##
## LEF for PtnCells ;
## created by Innovus v15.23-s045_1 on Fri Mar 20 02:54:40 2026
##

VERSION 5.8 ;

BUSBITCHARS "[]" ;
DIVIDERCHAR "/" ;

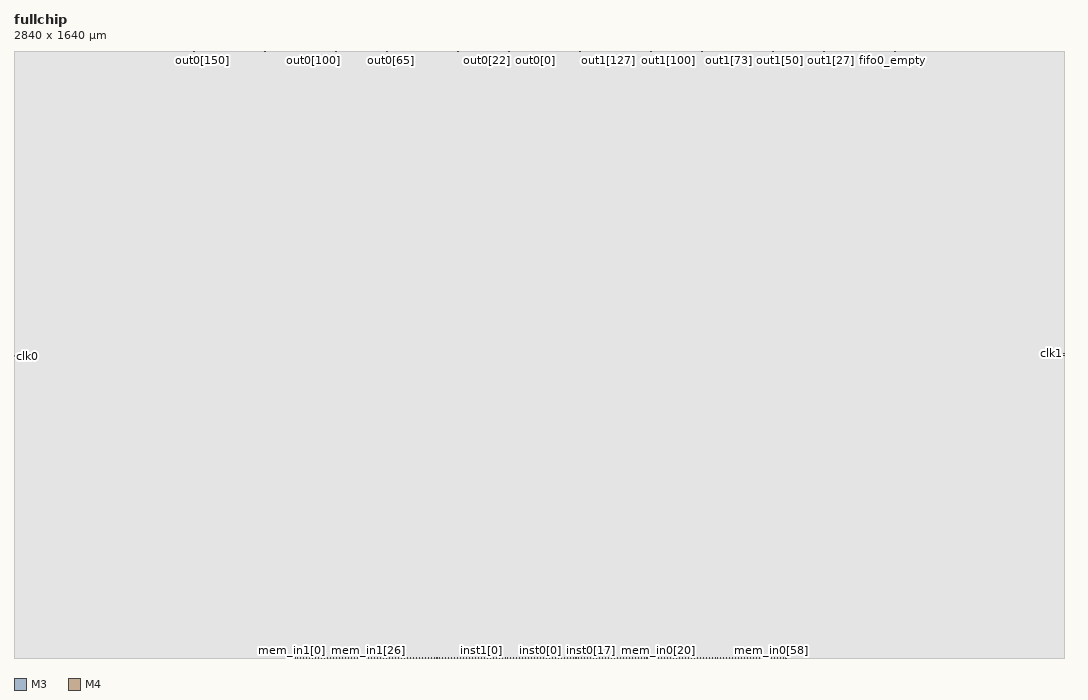
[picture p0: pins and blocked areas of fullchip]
MACRO fullchip
  CLASS BLOCK ;
  SIZE 2840.0000 BY 1640.0000 ;
  FOREIGN fullchip 0.0000 0.0000 ;
  ORIGIN 0 0 ;
  SYMMETRY X Y R90 ;
  PIN clk0
    DIRECTION INPUT ;
    USE SIGNAL ;
    PORT
      LAYER M3 ;
        RECT 0.0000 816.7500 0.5200 816.8500 ;
    END
  END clk0
  PIN clk1
    DIRECTION INPUT ;
    USE SIGNAL ;
    PORT
      LAYER M3 ;
        RECT 2839.4800 823.1500 2840.0000 823.2500 ;
    END
  END clk1
  PIN mem_in0[63]
    DIRECTION INPUT ;
    USE SIGNAL ;
    PORT
      LAYER M4 ;
        RECT 2088.0500 0.0000 2088.1500 0.5200 ;
    END
  END mem_in0[63]
  PIN mem_in0[62]
    DIRECTION INPUT ;
    USE SIGNAL ;
    PORT
      LAYER M4 ;
        RECT 2080.0500 0.0000 2080.1500 0.5200 ;
    END
  END mem_in0[62]
  PIN mem_in0[61]
    DIRECTION INPUT ;
    USE SIGNAL ;
    PORT
      LAYER M4 ;
        RECT 2072.0500 0.0000 2072.1500 0.5200 ;
    END
  END mem_in0[61]
  PIN mem_in0[60]
    DIRECTION INPUT ;
    USE SIGNAL ;
    PORT
      LAYER M4 ;
        RECT 2064.0500 0.0000 2064.1500 0.5200 ;
    END
  END mem_in0[60]
  PIN mem_in0[59]
    DIRECTION INPUT ;
    USE SIGNAL ;
    PORT
      LAYER M4 ;
        RECT 2056.0500 0.0000 2056.1500 0.5200 ;
    END
  END mem_in0[59]
  PIN mem_in0[58]
    DIRECTION INPUT ;
    USE SIGNAL ;
    PORT
      LAYER M4 ;
        RECT 2048.0500 0.0000 2048.1500 0.5200 ;
    END
  END mem_in0[58]
  PIN mem_in0[57]
    DIRECTION INPUT ;
    USE SIGNAL ;
    PORT
      LAYER M4 ;
        RECT 2040.0500 0.0000 2040.1500 0.5200 ;
    END
  END mem_in0[57]
  PIN mem_in0[56]
    DIRECTION INPUT ;
    USE SIGNAL ;
    PORT
      LAYER M4 ;
        RECT 2032.0500 0.0000 2032.1500 0.5200 ;
    END
  END mem_in0[56]
  PIN mem_in0[55]
    DIRECTION INPUT ;
    USE SIGNAL ;
    PORT
      LAYER M4 ;
        RECT 2024.0500 0.0000 2024.1500 0.5200 ;
    END
  END mem_in0[55]
  PIN mem_in0[54]
    DIRECTION INPUT ;
    USE SIGNAL ;
    PORT
      LAYER M4 ;
        RECT 2016.0500 0.0000 2016.1500 0.5200 ;
    END
  END mem_in0[54]
  PIN mem_in0[53]
    DIRECTION INPUT ;
    USE SIGNAL ;
    PORT
      LAYER M4 ;
        RECT 2008.0500 0.0000 2008.1500 0.5200 ;
    END
  END mem_in0[53]
  PIN mem_in0[52]
    DIRECTION INPUT ;
    USE SIGNAL ;
    PORT
      LAYER M4 ;
        RECT 2000.0500 0.0000 2000.1500 0.5200 ;
    END
  END mem_in0[52]
  PIN mem_in0[51]
    DIRECTION INPUT ;
    USE SIGNAL ;
    PORT
      LAYER M4 ;
        RECT 1992.0500 0.0000 1992.1500 0.5200 ;
    END
  END mem_in0[51]
  PIN mem_in0[50]
    DIRECTION INPUT ;
    USE SIGNAL ;
    PORT
      LAYER M4 ;
        RECT 1984.0500 0.0000 1984.1500 0.5200 ;
    END
  END mem_in0[50]
  PIN mem_in0[49]
    DIRECTION INPUT ;
    USE SIGNAL ;
    PORT
      LAYER M4 ;
        RECT 1976.0500 0.0000 1976.1500 0.5200 ;
    END
  END mem_in0[49]
  PIN mem_in0[48]
    DIRECTION INPUT ;
    USE SIGNAL ;
    PORT
      LAYER M4 ;
        RECT 1968.0500 0.0000 1968.1500 0.5200 ;
    END
  END mem_in0[48]
  PIN mem_in0[47]
    DIRECTION INPUT ;
    USE SIGNAL ;
    PORT
      LAYER M4 ;
        RECT 1960.0500 0.0000 1960.1500 0.5200 ;
    END
  END mem_in0[47]
  PIN mem_in0[46]
    DIRECTION INPUT ;
    USE SIGNAL ;
    PORT
      LAYER M4 ;
        RECT 1952.0500 0.0000 1952.1500 0.5200 ;
    END
  END mem_in0[46]
  PIN mem_in0[45]
    DIRECTION INPUT ;
    USE SIGNAL ;
    PORT
      LAYER M4 ;
        RECT 1944.0500 0.0000 1944.1500 0.5200 ;
    END
  END mem_in0[45]
  PIN mem_in0[44]
    DIRECTION INPUT ;
    USE SIGNAL ;
    PORT
      LAYER M4 ;
        RECT 1936.0500 0.0000 1936.1500 0.5200 ;
    END
  END mem_in0[44]
  PIN mem_in0[43]
    DIRECTION INPUT ;
    USE SIGNAL ;
    PORT
      LAYER M4 ;
        RECT 1928.0500 0.0000 1928.1500 0.5200 ;
    END
  END mem_in0[43]
  PIN mem_in0[42]
    DIRECTION INPUT ;
    USE SIGNAL ;
    PORT
      LAYER M4 ;
        RECT 1920.0500 0.0000 1920.1500 0.5200 ;
    END
  END mem_in0[42]
  PIN mem_in0[41]
    DIRECTION INPUT ;
    USE SIGNAL ;
    PORT
      LAYER M4 ;
        RECT 1912.0500 0.0000 1912.1500 0.5200 ;
    END
  END mem_in0[41]
  PIN mem_in0[40]
    DIRECTION INPUT ;
    USE SIGNAL ;
    PORT
      LAYER M4 ;
        RECT 1904.0500 0.0000 1904.1500 0.5200 ;
    END
  END mem_in0[40]
  PIN mem_in0[39]
    DIRECTION INPUT ;
    USE SIGNAL ;
    PORT
      LAYER M4 ;
        RECT 1896.0500 0.0000 1896.1500 0.5200 ;
    END
  END mem_in0[39]
  PIN mem_in0[38]
    DIRECTION INPUT ;
    USE SIGNAL ;
    PORT
      LAYER M4 ;
        RECT 1888.0500 0.0000 1888.1500 0.5200 ;
    END
  END mem_in0[38]
  PIN mem_in0[37]
    DIRECTION INPUT ;
    USE SIGNAL ;
    PORT
      LAYER M4 ;
        RECT 1880.0500 0.0000 1880.1500 0.5200 ;
    END
  END mem_in0[37]
  PIN mem_in0[36]
    DIRECTION INPUT ;
    USE SIGNAL ;
    PORT
      LAYER M4 ;
        RECT 1872.0500 0.0000 1872.1500 0.5200 ;
    END
  END mem_in0[36]
  PIN mem_in0[35]
    DIRECTION INPUT ;
    USE SIGNAL ;
    PORT
      LAYER M4 ;
        RECT 1864.0500 0.0000 1864.1500 0.5200 ;
    END
  END mem_in0[35]
  PIN mem_in0[34]
    DIRECTION INPUT ;
    USE SIGNAL ;
    PORT
      LAYER M4 ;
        RECT 1856.0500 0.0000 1856.1500 0.5200 ;
    END
  END mem_in0[34]
  PIN mem_in0[33]
    DIRECTION INPUT ;
    USE SIGNAL ;
    PORT
      LAYER M4 ;
        RECT 1848.0500 0.0000 1848.1500 0.5200 ;
    END
  END mem_in0[33]
  PIN mem_in0[32]
    DIRECTION INPUT ;
    USE SIGNAL ;
    PORT
      LAYER M4 ;
        RECT 1840.0500 0.0000 1840.1500 0.5200 ;
    END
  END mem_in0[32]
  PIN mem_in0[31]
    DIRECTION INPUT ;
    USE SIGNAL ;
    PORT
      LAYER M4 ;
        RECT 1832.0500 0.0000 1832.1500 0.5200 ;
    END
  END mem_in0[31]
  PIN mem_in0[30]
    DIRECTION INPUT ;
    USE SIGNAL ;
    PORT
      LAYER M4 ;
        RECT 1824.0500 0.0000 1824.1500 0.5200 ;
    END
  END mem_in0[30]
  PIN mem_in0[29]
    DIRECTION INPUT ;
    USE SIGNAL ;
    PORT
      LAYER M4 ;
        RECT 1816.0500 0.0000 1816.1500 0.5200 ;
    END
  END mem_in0[29]
  PIN mem_in0[28]
    DIRECTION INPUT ;
    USE SIGNAL ;
    PORT
      LAYER M4 ;
        RECT 1808.0500 0.0000 1808.1500 0.5200 ;
    END
  END mem_in0[28]
  PIN mem_in0[27]
    DIRECTION INPUT ;
    USE SIGNAL ;
    PORT
      LAYER M4 ;
        RECT 1800.0500 0.0000 1800.1500 0.5200 ;
    END
  END mem_in0[27]
  PIN mem_in0[26]
    DIRECTION INPUT ;
    USE SIGNAL ;
    PORT
      LAYER M4 ;
        RECT 1792.0500 0.0000 1792.1500 0.5200 ;
    END
  END mem_in0[26]
  PIN mem_in0[25]
    DIRECTION INPUT ;
    USE SIGNAL ;
    PORT
      LAYER M4 ;
        RECT 1784.0500 0.0000 1784.1500 0.5200 ;
    END
  END mem_in0[25]
  PIN mem_in0[24]
    DIRECTION INPUT ;
    USE SIGNAL ;
    PORT
      LAYER M4 ;
        RECT 1776.0500 0.0000 1776.1500 0.5200 ;
    END
  END mem_in0[24]
  PIN mem_in0[23]
    DIRECTION INPUT ;
    USE SIGNAL ;
    PORT
      LAYER M4 ;
        RECT 1768.0500 0.0000 1768.1500 0.5200 ;
    END
  END mem_in0[23]
  PIN mem_in0[22]
    DIRECTION INPUT ;
    USE SIGNAL ;
    PORT
      LAYER M4 ;
        RECT 1760.0500 0.0000 1760.1500 0.5200 ;
    END
  END mem_in0[22]
  PIN mem_in0[21]
    DIRECTION INPUT ;
    USE SIGNAL ;
    PORT
      LAYER M4 ;
        RECT 1752.0500 0.0000 1752.1500 0.5200 ;
    END
  END mem_in0[21]
  PIN mem_in0[20]
    DIRECTION INPUT ;
    USE SIGNAL ;
    PORT
      LAYER M4 ;
        RECT 1744.0500 0.0000 1744.1500 0.5200 ;
    END
  END mem_in0[20]
  PIN mem_in0[19]
    DIRECTION INPUT ;
    USE SIGNAL ;
    PORT
      LAYER M4 ;
        RECT 1736.0500 0.0000 1736.1500 0.5200 ;
    END
  END mem_in0[19]
  PIN mem_in0[18]
    DIRECTION INPUT ;
    USE SIGNAL ;
    PORT
      LAYER M4 ;
        RECT 1728.0500 0.0000 1728.1500 0.5200 ;
    END
  END mem_in0[18]
  PIN mem_in0[17]
    DIRECTION INPUT ;
    USE SIGNAL ;
    PORT
      LAYER M4 ;
        RECT 1720.0500 0.0000 1720.1500 0.5200 ;
    END
  END mem_in0[17]
  PIN mem_in0[16]
    DIRECTION INPUT ;
    USE SIGNAL ;
    PORT
      LAYER M4 ;
        RECT 1712.0500 0.0000 1712.1500 0.5200 ;
    END
  END mem_in0[16]
  PIN mem_in0[15]
    DIRECTION INPUT ;
    USE SIGNAL ;
    PORT
      LAYER M4 ;
        RECT 1704.0500 0.0000 1704.1500 0.5200 ;
    END
  END mem_in0[15]
  PIN mem_in0[14]
    DIRECTION INPUT ;
    USE SIGNAL ;
    PORT
      LAYER M4 ;
        RECT 1696.0500 0.0000 1696.1500 0.5200 ;
    END
  END mem_in0[14]
  PIN mem_in0[13]
    DIRECTION INPUT ;
    USE SIGNAL ;
    PORT
      LAYER M4 ;
        RECT 1688.0500 0.0000 1688.1500 0.5200 ;
    END
  END mem_in0[13]
  PIN mem_in0[12]
    DIRECTION INPUT ;
    USE SIGNAL ;
    PORT
      LAYER M4 ;
        RECT 1680.0500 0.0000 1680.1500 0.5200 ;
    END
  END mem_in0[12]
  PIN mem_in0[11]
    DIRECTION INPUT ;
    USE SIGNAL ;
    PORT
      LAYER M4 ;
        RECT 1672.0500 0.0000 1672.1500 0.5200 ;
    END
  END mem_in0[11]
  PIN mem_in0[10]
    DIRECTION INPUT ;
    USE SIGNAL ;
    PORT
      LAYER M4 ;
        RECT 1664.0500 0.0000 1664.1500 0.5200 ;
    END
  END mem_in0[10]
  PIN mem_in0[9]
    DIRECTION INPUT ;
    USE SIGNAL ;
    PORT
      LAYER M4 ;
        RECT 1656.0500 0.0000 1656.1500 0.5200 ;
    END
  END mem_in0[9]
  PIN mem_in0[8]
    DIRECTION INPUT ;
    USE SIGNAL ;
    PORT
      LAYER M4 ;
        RECT 1648.0500 0.0000 1648.1500 0.5200 ;
    END
  END mem_in0[8]
  PIN mem_in0[7]
    DIRECTION INPUT ;
    USE SIGNAL ;
    PORT
      LAYER M4 ;
        RECT 1640.0500 0.0000 1640.1500 0.5200 ;
    END
  END mem_in0[7]
  PIN mem_in0[6]
    DIRECTION INPUT ;
    USE SIGNAL ;
    PORT
      LAYER M4 ;
        RECT 1632.0500 0.0000 1632.1500 0.5200 ;
    END
  END mem_in0[6]
  PIN mem_in0[5]
    DIRECTION INPUT ;
    USE SIGNAL ;
    PORT
      LAYER M4 ;
        RECT 1624.0500 0.0000 1624.1500 0.5200 ;
    END
  END mem_in0[5]
  PIN mem_in0[4]
    DIRECTION INPUT ;
    USE SIGNAL ;
    PORT
      LAYER M4 ;
        RECT 1616.0500 0.0000 1616.1500 0.5200 ;
    END
  END mem_in0[4]
  PIN mem_in0[3]
    DIRECTION INPUT ;
    USE SIGNAL ;
    PORT
      LAYER M4 ;
        RECT 1608.0500 0.0000 1608.1500 0.5200 ;
    END
  END mem_in0[3]
  PIN mem_in0[2]
    DIRECTION INPUT ;
    USE SIGNAL ;
    PORT
      LAYER M4 ;
        RECT 1600.0500 0.0000 1600.1500 0.5200 ;
    END
  END mem_in0[2]
  PIN mem_in0[1]
    DIRECTION INPUT ;
    USE SIGNAL ;
    PORT
      LAYER M4 ;
        RECT 1592.0500 0.0000 1592.1500 0.5200 ;
    END
  END mem_in0[1]
  PIN mem_in0[0]
    DIRECTION INPUT ;
    USE SIGNAL ;
    PORT
      LAYER M4 ;
        RECT 1584.0500 0.0000 1584.1500 0.5200 ;
    END
  END mem_in0[0]
  PIN mem_in1[63]
    DIRECTION INPUT ;
    USE SIGNAL ;
    PORT
      LAYER M4 ;
        RECT 1256.0500 0.0000 1256.1500 0.5200 ;
    END
  END mem_in1[63]
  PIN mem_in1[62]
    DIRECTION INPUT ;
    USE SIGNAL ;
    PORT
      LAYER M4 ;
        RECT 1248.0500 0.0000 1248.1500 0.5200 ;
    END
  END mem_in1[62]
  PIN mem_in1[61]
    DIRECTION INPUT ;
    USE SIGNAL ;
    PORT
      LAYER M4 ;
        RECT 1240.0500 0.0000 1240.1500 0.5200 ;
    END
  END mem_in1[61]
  PIN mem_in1[60]
    DIRECTION INPUT ;
    USE SIGNAL ;
    PORT
      LAYER M4 ;
        RECT 1232.0500 0.0000 1232.1500 0.5200 ;
    END
  END mem_in1[60]
  PIN mem_in1[59]
    DIRECTION INPUT ;
    USE SIGNAL ;
    PORT
      LAYER M4 ;
        RECT 1224.0500 0.0000 1224.1500 0.5200 ;
    END
  END mem_in1[59]
  PIN mem_in1[58]
    DIRECTION INPUT ;
    USE SIGNAL ;
    PORT
      LAYER M4 ;
        RECT 1216.0500 0.0000 1216.1500 0.5200 ;
    END
  END mem_in1[58]
  PIN mem_in1[57]
    DIRECTION INPUT ;
    USE SIGNAL ;
    PORT
      LAYER M4 ;
        RECT 1208.0500 0.0000 1208.1500 0.5200 ;
    END
  END mem_in1[57]
  PIN mem_in1[56]
    DIRECTION INPUT ;
    USE SIGNAL ;
    PORT
      LAYER M4 ;
        RECT 1200.0500 0.0000 1200.1500 0.5200 ;
    END
  END mem_in1[56]
  PIN mem_in1[55]
    DIRECTION INPUT ;
    USE SIGNAL ;
    PORT
      LAYER M4 ;
        RECT 1192.0500 0.0000 1192.1500 0.5200 ;
    END
  END mem_in1[55]
  PIN mem_in1[54]
    DIRECTION INPUT ;
    USE SIGNAL ;
    PORT
      LAYER M4 ;
        RECT 1184.0500 0.0000 1184.1500 0.5200 ;
    END
  END mem_in1[54]
  PIN mem_in1[53]
    DIRECTION INPUT ;
    USE SIGNAL ;
    PORT
      LAYER M4 ;
        RECT 1176.0500 0.0000 1176.1500 0.5200 ;
    END
  END mem_in1[53]
  PIN mem_in1[52]
    DIRECTION INPUT ;
    USE SIGNAL ;
    PORT
      LAYER M4 ;
        RECT 1168.0500 0.0000 1168.1500 0.5200 ;
    END
  END mem_in1[52]
  PIN mem_in1[51]
    DIRECTION INPUT ;
    USE SIGNAL ;
    PORT
      LAYER M4 ;
        RECT 1160.0500 0.0000 1160.1500 0.5200 ;
    END
  END mem_in1[51]
  PIN mem_in1[50]
    DIRECTION INPUT ;
    USE SIGNAL ;
    PORT
      LAYER M4 ;
        RECT 1152.0500 0.0000 1152.1500 0.5200 ;
    END
  END mem_in1[50]
  PIN mem_in1[49]
    DIRECTION INPUT ;
    USE SIGNAL ;
    PORT
      LAYER M4 ;
        RECT 1144.0500 0.0000 1144.1500 0.5200 ;
    END
  END mem_in1[49]
  PIN mem_in1[48]
    DIRECTION INPUT ;
    USE SIGNAL ;
    PORT
      LAYER M4 ;
        RECT 1136.0500 0.0000 1136.1500 0.5200 ;
    END
  END mem_in1[48]
  PIN mem_in1[47]
    DIRECTION INPUT ;
    USE SIGNAL ;
    PORT
      LAYER M4 ;
        RECT 1128.0500 0.0000 1128.1500 0.5200 ;
    END
  END mem_in1[47]
  PIN mem_in1[46]
    DIRECTION INPUT ;
    USE SIGNAL ;
    PORT
      LAYER M4 ;
        RECT 1120.0500 0.0000 1120.1500 0.5200 ;
    END
  END mem_in1[46]
  PIN mem_in1[45]
    DIRECTION INPUT ;
    USE SIGNAL ;
    PORT
      LAYER M4 ;
        RECT 1112.0500 0.0000 1112.1500 0.5200 ;
    END
  END mem_in1[45]
  PIN mem_in1[44]
    DIRECTION INPUT ;
    USE SIGNAL ;
    PORT
      LAYER M4 ;
        RECT 1104.0500 0.0000 1104.1500 0.5200 ;
    END
  END mem_in1[44]
  PIN mem_in1[43]
    DIRECTION INPUT ;
    USE SIGNAL ;
    PORT
      LAYER M4 ;
        RECT 1096.0500 0.0000 1096.1500 0.5200 ;
    END
  END mem_in1[43]
  PIN mem_in1[42]
    DIRECTION INPUT ;
    USE SIGNAL ;
    PORT
      LAYER M4 ;
        RECT 1088.0500 0.0000 1088.1500 0.5200 ;
    END
  END mem_in1[42]
  PIN mem_in1[41]
    DIRECTION INPUT ;
    USE SIGNAL ;
    PORT
      LAYER M4 ;
        RECT 1080.0500 0.0000 1080.1500 0.5200 ;
    END
  END mem_in1[41]
  PIN mem_in1[40]
    DIRECTION INPUT ;
    USE SIGNAL ;
    PORT
      LAYER M4 ;
        RECT 1072.0500 0.0000 1072.1500 0.5200 ;
    END
  END mem_in1[40]
  PIN mem_in1[39]
    DIRECTION INPUT ;
    USE SIGNAL ;
    PORT
      LAYER M4 ;
        RECT 1064.0500 0.0000 1064.1500 0.5200 ;
    END
  END mem_in1[39]
  PIN mem_in1[38]
    DIRECTION INPUT ;
    USE SIGNAL ;
    PORT
      LAYER M4 ;
        RECT 1056.0500 0.0000 1056.1500 0.5200 ;
    END
  END mem_in1[38]
  PIN mem_in1[37]
    DIRECTION INPUT ;
    USE SIGNAL ;
    PORT
      LAYER M4 ;
        RECT 1048.0500 0.0000 1048.1500 0.5200 ;
    END
  END mem_in1[37]
  PIN mem_in1[36]
    DIRECTION INPUT ;
    USE SIGNAL ;
    PORT
      LAYER M4 ;
        RECT 1040.0500 0.0000 1040.1500 0.5200 ;
    END
  END mem_in1[36]
  PIN mem_in1[35]
    DIRECTION INPUT ;
    USE SIGNAL ;
    PORT
      LAYER M4 ;
        RECT 1032.0500 0.0000 1032.1500 0.5200 ;
    END
  END mem_in1[35]
  PIN mem_in1[34]
    DIRECTION INPUT ;
    USE SIGNAL ;
    PORT
      LAYER M4 ;
        RECT 1024.0500 0.0000 1024.1500 0.5200 ;
    END
  END mem_in1[34]
  PIN mem_in1[33]
    DIRECTION INPUT ;
    USE SIGNAL ;
    PORT
      LAYER M4 ;
        RECT 1016.0500 0.0000 1016.1500 0.5200 ;
    END
  END mem_in1[33]
  PIN mem_in1[32]
    DIRECTION INPUT ;
    USE SIGNAL ;
    PORT
      LAYER M4 ;
        RECT 1008.0500 0.0000 1008.1500 0.5200 ;
    END
  END mem_in1[32]
  PIN mem_in1[31]
    DIRECTION INPUT ;
    USE SIGNAL ;
    PORT
      LAYER M4 ;
        RECT 1000.0500 0.0000 1000.1500 0.5200 ;
    END
  END mem_in1[31]
  PIN mem_in1[30]
    DIRECTION INPUT ;
    USE SIGNAL ;
    PORT
      LAYER M4 ;
        RECT 992.0500 0.0000 992.1500 0.5200 ;
    END
  END mem_in1[30]
  PIN mem_in1[29]
    DIRECTION INPUT ;
    USE SIGNAL ;
    PORT
      LAYER M4 ;
        RECT 984.0500 0.0000 984.1500 0.5200 ;
    END
  END mem_in1[29]
  PIN mem_in1[28]
    DIRECTION INPUT ;
    USE SIGNAL ;
    PORT
      LAYER M4 ;
        RECT 976.0500 0.0000 976.1500 0.5200 ;
    END
  END mem_in1[28]
  PIN mem_in1[27]
    DIRECTION INPUT ;
    USE SIGNAL ;
    PORT
      LAYER M4 ;
        RECT 968.0500 0.0000 968.1500 0.5200 ;
    END
  END mem_in1[27]
  PIN mem_in1[26]
    DIRECTION INPUT ;
    USE SIGNAL ;
    PORT
      LAYER M4 ;
        RECT 960.0500 0.0000 960.1500 0.5200 ;
    END
  END mem_in1[26]
  PIN mem_in1[25]
    DIRECTION INPUT ;
    USE SIGNAL ;
    PORT
      LAYER M4 ;
        RECT 952.0500 0.0000 952.1500 0.5200 ;
    END
  END mem_in1[25]
  PIN mem_in1[24]
    DIRECTION INPUT ;
    USE SIGNAL ;
    PORT
      LAYER M4 ;
        RECT 944.0500 0.0000 944.1500 0.5200 ;
    END
  END mem_in1[24]
  PIN mem_in1[23]
    DIRECTION INPUT ;
    USE SIGNAL ;
    PORT
      LAYER M4 ;
        RECT 936.0500 0.0000 936.1500 0.5200 ;
    END
  END mem_in1[23]
  PIN mem_in1[22]
    DIRECTION INPUT ;
    USE SIGNAL ;
    PORT
      LAYER M4 ;
        RECT 928.0500 0.0000 928.1500 0.5200 ;
    END
  END mem_in1[22]
  PIN mem_in1[21]
    DIRECTION INPUT ;
    USE SIGNAL ;
    PORT
      LAYER M4 ;
        RECT 920.0500 0.0000 920.1500 0.5200 ;
    END
  END mem_in1[21]
  PIN mem_in1[20]
    DIRECTION INPUT ;
    USE SIGNAL ;
    PORT
      LAYER M4 ;
        RECT 912.0500 0.0000 912.1500 0.5200 ;
    END
  END mem_in1[20]
  PIN mem_in1[19]
    DIRECTION INPUT ;
    USE SIGNAL ;
    PORT
      LAYER M4 ;
        RECT 904.0500 0.0000 904.1500 0.5200 ;
    END
  END mem_in1[19]
  PIN mem_in1[18]
    DIRECTION INPUT ;
    USE SIGNAL ;
    PORT
      LAYER M4 ;
        RECT 896.0500 0.0000 896.1500 0.5200 ;
    END
  END mem_in1[18]
  PIN mem_in1[17]
    DIRECTION INPUT ;
    USE SIGNAL ;
    PORT
      LAYER M4 ;
        RECT 888.0500 0.0000 888.1500 0.5200 ;
    END
  END mem_in1[17]
  PIN mem_in1[16]
    DIRECTION INPUT ;
    USE SIGNAL ;
    PORT
      LAYER M4 ;
        RECT 880.0500 0.0000 880.1500 0.5200 ;
    END
  END mem_in1[16]
  PIN mem_in1[15]
    DIRECTION INPUT ;
    USE SIGNAL ;
    PORT
      LAYER M4 ;
        RECT 872.0500 0.0000 872.1500 0.5200 ;
    END
  END mem_in1[15]
  PIN mem_in1[14]
    DIRECTION INPUT ;
    USE SIGNAL ;
    PORT
      LAYER M4 ;
        RECT 864.0500 0.0000 864.1500 0.5200 ;
    END
  END mem_in1[14]
  PIN mem_in1[13]
    DIRECTION INPUT ;
    USE SIGNAL ;
    PORT
      LAYER M4 ;
        RECT 856.0500 0.0000 856.1500 0.5200 ;
    END
  END mem_in1[13]
  PIN mem_in1[12]
    DIRECTION INPUT ;
    USE SIGNAL ;
    PORT
      LAYER M4 ;
        RECT 848.0500 0.0000 848.1500 0.5200 ;
    END
  END mem_in1[12]
  PIN mem_in1[11]
    DIRECTION INPUT ;
    USE SIGNAL ;
    PORT
      LAYER M4 ;
        RECT 840.0500 0.0000 840.1500 0.5200 ;
    END
  END mem_in1[11]
  PIN mem_in1[10]
    DIRECTION INPUT ;
    USE SIGNAL ;
    PORT
      LAYER M4 ;
        RECT 832.0500 0.0000 832.1500 0.5200 ;
    END
  END mem_in1[10]
  PIN mem_in1[9]
    DIRECTION INPUT ;
    USE SIGNAL ;
    PORT
      LAYER M4 ;
        RECT 824.0500 0.0000 824.1500 0.5200 ;
    END
  END mem_in1[9]
  PIN mem_in1[8]
    DIRECTION INPUT ;
    USE SIGNAL ;
    PORT
      LAYER M4 ;
        RECT 816.0500 0.0000 816.1500 0.5200 ;
    END
  END mem_in1[8]
  PIN mem_in1[7]
    DIRECTION INPUT ;
    USE SIGNAL ;
    PORT
      LAYER M4 ;
        RECT 808.0500 0.0000 808.1500 0.5200 ;
    END
  END mem_in1[7]
  PIN mem_in1[6]
    DIRECTION INPUT ;
    USE SIGNAL ;
    PORT
      LAYER M4 ;
        RECT 800.0500 0.0000 800.1500 0.5200 ;
    END
  END mem_in1[6]
  PIN mem_in1[5]
    DIRECTION INPUT ;
    USE SIGNAL ;
    PORT
      LAYER M4 ;
        RECT 792.0500 0.0000 792.1500 0.5200 ;
    END
  END mem_in1[5]
  PIN mem_in1[4]
    DIRECTION INPUT ;
    USE SIGNAL ;
    PORT
      LAYER M4 ;
        RECT 784.0500 0.0000 784.1500 0.5200 ;
    END
  END mem_in1[4]
  PIN mem_in1[3]
    DIRECTION INPUT ;
    USE SIGNAL ;
    PORT
      LAYER M4 ;
        RECT 776.0500 0.0000 776.1500 0.5200 ;
    END
  END mem_in1[3]
  PIN mem_in1[2]
    DIRECTION INPUT ;
    USE SIGNAL ;
    PORT
      LAYER M4 ;
        RECT 768.0500 0.0000 768.1500 0.5200 ;
    END
  END mem_in1[2]
  PIN mem_in1[1]
    DIRECTION INPUT ;
    USE SIGNAL ;
    PORT
      LAYER M4 ;
        RECT 760.0500 0.0000 760.1500 0.5200 ;
    END
  END mem_in1[1]
  PIN mem_in1[0]
    DIRECTION INPUT ;
    USE SIGNAL ;
    PORT
      LAYER M4 ;
        RECT 752.0500 0.0000 752.1500 0.5200 ;
    END
  END mem_in1[0]
  PIN inst0[19]
    DIRECTION INPUT ;
    USE SIGNAL ;
    PORT
      LAYER M4 ;
        RECT 1576.0500 0.0000 1576.1500 0.5200 ;
    END
  END inst0[19]
  PIN inst0[18]
    DIRECTION INPUT ;
    USE SIGNAL ;
    PORT
      LAYER M4 ;
        RECT 1568.0500 0.0000 1568.1500 0.5200 ;
    END
  END inst0[18]
  PIN inst0[17]
    DIRECTION INPUT ;
    USE SIGNAL ;
    PORT
      LAYER M4 ;
        RECT 1560.0500 0.0000 1560.1500 0.5200 ;
    END
  END inst0[17]
  PIN inst0[16]
    DIRECTION INPUT ;
    USE SIGNAL ;
    PORT
      LAYER M4 ;
        RECT 1552.0500 0.0000 1552.1500 0.5200 ;
    END
  END inst0[16]
  PIN inst0[15]
    DIRECTION INPUT ;
    USE SIGNAL ;
    PORT
      LAYER M4 ;
        RECT 1544.0500 0.0000 1544.1500 0.5200 ;
    END
  END inst0[15]
  PIN inst0[14]
    DIRECTION INPUT ;
    USE SIGNAL ;
    PORT
      LAYER M4 ;
        RECT 1536.0500 0.0000 1536.1500 0.5200 ;
    END
  END inst0[14]
  PIN inst0[13]
    DIRECTION INPUT ;
    USE SIGNAL ;
    PORT
      LAYER M4 ;
        RECT 1528.0500 0.0000 1528.1500 0.5200 ;
    END
  END inst0[13]
  PIN inst0[12]
    DIRECTION INPUT ;
    USE SIGNAL ;
    PORT
      LAYER M4 ;
        RECT 1520.0500 0.0000 1520.1500 0.5200 ;
    END
  END inst0[12]
  PIN inst0[11]
    DIRECTION INPUT ;
    USE SIGNAL ;
    PORT
      LAYER M4 ;
        RECT 1512.0500 0.0000 1512.1500 0.5200 ;
    END
  END inst0[11]
  PIN inst0[10]
    DIRECTION INPUT ;
    USE SIGNAL ;
    PORT
      LAYER M4 ;
        RECT 1504.0500 0.0000 1504.1500 0.5200 ;
    END
  END inst0[10]
  PIN inst0[9]
    DIRECTION INPUT ;
    USE SIGNAL ;
    PORT
      LAYER M4 ;
        RECT 1496.0500 0.0000 1496.1500 0.5200 ;
    END
  END inst0[9]
  PIN inst0[8]
    DIRECTION INPUT ;
    USE SIGNAL ;
    PORT
      LAYER M4 ;
        RECT 1488.0500 0.0000 1488.1500 0.5200 ;
    END
  END inst0[8]
  PIN inst0[7]
    DIRECTION INPUT ;
    USE SIGNAL ;
    PORT
      LAYER M4 ;
        RECT 1480.0500 0.0000 1480.1500 0.5200 ;
    END
  END inst0[7]
  PIN inst0[6]
    DIRECTION INPUT ;
    USE SIGNAL ;
    PORT
      LAYER M4 ;
        RECT 1472.0500 0.0000 1472.1500 0.5200 ;
    END
  END inst0[6]
  PIN inst0[5]
    DIRECTION INPUT ;
    USE SIGNAL ;
    PORT
      LAYER M4 ;
        RECT 1464.0500 0.0000 1464.1500 0.5200 ;
    END
  END inst0[5]
  PIN inst0[4]
    DIRECTION INPUT ;
    USE SIGNAL ;
    PORT
      LAYER M4 ;
        RECT 1456.0500 0.0000 1456.1500 0.5200 ;
    END
  END inst0[4]
  PIN inst0[3]
    DIRECTION INPUT ;
    USE SIGNAL ;
    PORT
      LAYER M4 ;
        RECT 1448.0500 0.0000 1448.1500 0.5200 ;
    END
  END inst0[3]
  PIN inst0[2]
    DIRECTION INPUT ;
    USE SIGNAL ;
    PORT
      LAYER M4 ;
        RECT 1440.0500 0.0000 1440.1500 0.5200 ;
    END
  END inst0[2]
  PIN inst0[1]
    DIRECTION INPUT ;
    USE SIGNAL ;
    PORT
      LAYER M4 ;
        RECT 1432.0500 0.0000 1432.1500 0.5200 ;
    END
  END inst0[1]
  PIN inst0[0]
    DIRECTION INPUT ;
    USE SIGNAL ;
    PORT
      LAYER M4 ;
        RECT 1424.0500 0.0000 1424.1500 0.5200 ;
    END
  END inst0[0]
  PIN inst1[19]
    DIRECTION INPUT ;
    USE SIGNAL ;
    PORT
      LAYER M4 ;
        RECT 1416.0500 0.0000 1416.1500 0.5200 ;
    END
  END inst1[19]
  PIN inst1[18]
    DIRECTION INPUT ;
    USE SIGNAL ;
    PORT
      LAYER M4 ;
        RECT 1408.0500 0.0000 1408.1500 0.5200 ;
    END
  END inst1[18]
  PIN inst1[17]
    DIRECTION INPUT ;
    USE SIGNAL ;
    PORT
      LAYER M4 ;
        RECT 1400.0500 0.0000 1400.1500 0.5200 ;
    END
  END inst1[17]
  PIN inst1[16]
    DIRECTION INPUT ;
    USE SIGNAL ;
    PORT
      LAYER M4 ;
        RECT 1392.0500 0.0000 1392.1500 0.5200 ;
    END
  END inst1[16]
  PIN inst1[15]
    DIRECTION INPUT ;
    USE SIGNAL ;
    PORT
      LAYER M4 ;
        RECT 1384.0500 0.0000 1384.1500 0.5200 ;
    END
  END inst1[15]
  PIN inst1[14]
    DIRECTION INPUT ;
    USE SIGNAL ;
    PORT
      LAYER M4 ;
        RECT 1376.0500 0.0000 1376.1500 0.5200 ;
    END
  END inst1[14]
  PIN inst1[13]
    DIRECTION INPUT ;
    USE SIGNAL ;
    PORT
      LAYER M4 ;
        RECT 1368.0500 0.0000 1368.1500 0.5200 ;
    END
  END inst1[13]
  PIN inst1[12]
    DIRECTION INPUT ;
    USE SIGNAL ;
    PORT
      LAYER M4 ;
        RECT 1360.0500 0.0000 1360.1500 0.5200 ;
    END
  END inst1[12]
  PIN inst1[11]
    DIRECTION INPUT ;
    USE SIGNAL ;
    PORT
      LAYER M4 ;
        RECT 1352.0500 0.0000 1352.1500 0.5200 ;
    END
  END inst1[11]
  PIN inst1[10]
    DIRECTION INPUT ;
    USE SIGNAL ;
    PORT
      LAYER M4 ;
        RECT 1344.0500 0.0000 1344.1500 0.5200 ;
    END
  END inst1[10]
  PIN inst1[9]
    DIRECTION INPUT ;
    USE SIGNAL ;
    PORT
      LAYER M4 ;
        RECT 1336.0500 0.0000 1336.1500 0.5200 ;
    END
  END inst1[9]
  PIN inst1[8]
    DIRECTION INPUT ;
    USE SIGNAL ;
    PORT
      LAYER M4 ;
        RECT 1328.0500 0.0000 1328.1500 0.5200 ;
    END
  END inst1[8]
  PIN inst1[7]
    DIRECTION INPUT ;
    USE SIGNAL ;
    PORT
      LAYER M4 ;
        RECT 1320.0500 0.0000 1320.1500 0.5200 ;
    END
  END inst1[7]
  PIN inst1[6]
    DIRECTION INPUT ;
    USE SIGNAL ;
    PORT
      LAYER M4 ;
        RECT 1312.0500 0.0000 1312.1500 0.5200 ;
    END
  END inst1[6]
  PIN inst1[5]
    DIRECTION INPUT ;
    USE SIGNAL ;
    PORT
      LAYER M4 ;
        RECT 1304.0500 0.0000 1304.1500 0.5200 ;
    END
  END inst1[5]
  PIN inst1[4]
    DIRECTION INPUT ;
    USE SIGNAL ;
    PORT
      LAYER M4 ;
        RECT 1296.0500 0.0000 1296.1500 0.5200 ;
    END
  END inst1[4]
  PIN inst1[3]
    DIRECTION INPUT ;
    USE SIGNAL ;
    PORT
      LAYER M4 ;
        RECT 1288.0500 0.0000 1288.1500 0.5200 ;
    END
  END inst1[3]
  PIN inst1[2]
    DIRECTION INPUT ;
    USE SIGNAL ;
    PORT
      LAYER M4 ;
        RECT 1280.0500 0.0000 1280.1500 0.5200 ;
    END
  END inst1[2]
  PIN inst1[1]
    DIRECTION INPUT ;
    USE SIGNAL ;
    PORT
      LAYER M4 ;
        RECT 1272.0500 0.0000 1272.1500 0.5200 ;
    END
  END inst1[1]
  PIN inst1[0]
    DIRECTION INPUT ;
    USE SIGNAL ;
    PORT
      LAYER M4 ;
        RECT 1264.0500 0.0000 1264.1500 0.5200 ;
    END
  END inst1[0]
  PIN reset0
    DIRECTION INPUT ;
    USE SIGNAL ;
    PORT
      LAYER M3 ;
        RECT 0.0000 822.7500 0.5200 822.8500 ;
    END
  END reset0
  PIN reset1
    DIRECTION INPUT ;
    USE SIGNAL ;
    PORT
      LAYER M3 ;
        RECT 2839.4800 817.1500 2840.0000 817.2500 ;
    END
  END reset1
  PIN out0[159]
    DIRECTION OUTPUT ;
    USE SIGNAL ;
    PORT
      LAYER M4 ;
        RECT 456.8500 1639.4800 456.9500 1640.0000 ;
    END
  END out0[159]
  PIN out0[158]
    DIRECTION OUTPUT ;
    USE SIGNAL ;
    PORT
      LAYER M4 ;
        RECT 462.8500 1639.4800 462.9500 1640.0000 ;
    END
  END out0[158]
  PIN out0[157]
    DIRECTION OUTPUT ;
    USE SIGNAL ;
    PORT
      LAYER M4 ;
        RECT 468.8500 1639.4800 468.9500 1640.0000 ;
    END
  END out0[157]
  PIN out0[156]
    DIRECTION OUTPUT ;
    USE SIGNAL ;
    PORT
      LAYER M4 ;
        RECT 474.8500 1639.4800 474.9500 1640.0000 ;
    END
  END out0[156]
  PIN out0[155]
    DIRECTION OUTPUT ;
    USE SIGNAL ;
    PORT
      LAYER M4 ;
        RECT 480.8500 1639.4800 480.9500 1640.0000 ;
    END
  END out0[155]
  PIN out0[154]
    DIRECTION OUTPUT ;
    USE SIGNAL ;
    PORT
      LAYER M4 ;
        RECT 486.8500 1639.4800 486.9500 1640.0000 ;
    END
  END out0[154]
  PIN out0[153]
    DIRECTION OUTPUT ;
    USE SIGNAL ;
    PORT
      LAYER M4 ;
        RECT 492.8500 1639.4800 492.9500 1640.0000 ;
    END
  END out0[153]
  PIN out0[152]
    DIRECTION OUTPUT ;
    USE SIGNAL ;
    PORT
      LAYER M4 ;
        RECT 498.8500 1639.4800 498.9500 1640.0000 ;
    END
  END out0[152]
  PIN out0[151]
    DIRECTION OUTPUT ;
    USE SIGNAL ;
    PORT
      LAYER M4 ;
        RECT 504.8500 1639.4800 504.9500 1640.0000 ;
    END
  END out0[151]
  PIN out0[150]
    DIRECTION OUTPUT ;
    USE SIGNAL ;
    PORT
      LAYER M4 ;
        RECT 510.8500 1639.4800 510.9500 1640.0000 ;
    END
  END out0[150]
  PIN out0[149]
    DIRECTION OUTPUT ;
    USE SIGNAL ;
    PORT
      LAYER M4 ;
        RECT 516.8500 1639.4800 516.9500 1640.0000 ;
    END
  END out0[149]
  PIN out0[148]
    DIRECTION OUTPUT ;
    USE SIGNAL ;
    PORT
      LAYER M4 ;
        RECT 522.8500 1639.4800 522.9500 1640.0000 ;
    END
  END out0[148]
  PIN out0[147]
    DIRECTION OUTPUT ;
    USE SIGNAL ;
    PORT
      LAYER M4 ;
        RECT 528.8500 1639.4800 528.9500 1640.0000 ;
    END
  END out0[147]
  PIN out0[146]
    DIRECTION OUTPUT ;
    USE SIGNAL ;
    PORT
      LAYER M4 ;
        RECT 534.8500 1639.4800 534.9500 1640.0000 ;
    END
  END out0[146]
  PIN out0[145]
    DIRECTION OUTPUT ;
    USE SIGNAL ;
    PORT
      LAYER M4 ;
        RECT 540.8500 1639.4800 540.9500 1640.0000 ;
    END
  END out0[145]
  PIN out0[144]
    DIRECTION OUTPUT ;
    USE SIGNAL ;
    PORT
      LAYER M4 ;
        RECT 546.8500 1639.4800 546.9500 1640.0000 ;
    END
  END out0[144]
  PIN out0[143]
    DIRECTION OUTPUT ;
    USE SIGNAL ;
    PORT
      LAYER M4 ;
        RECT 552.8500 1639.4800 552.9500 1640.0000 ;
    END
  END out0[143]
  PIN out0[142]
    DIRECTION OUTPUT ;
    USE SIGNAL ;
    PORT
      LAYER M4 ;
        RECT 558.8500 1639.4800 558.9500 1640.0000 ;
    END
  END out0[142]
  PIN out0[141]
    DIRECTION OUTPUT ;
    USE SIGNAL ;
    PORT
      LAYER M4 ;
        RECT 564.8500 1639.4800 564.9500 1640.0000 ;
    END
  END out0[141]
  PIN out0[140]
    DIRECTION OUTPUT ;
    USE SIGNAL ;
    PORT
      LAYER M4 ;
        RECT 570.8500 1639.4800 570.9500 1640.0000 ;
    END
  END out0[140]
  PIN out0[139]
    DIRECTION OUTPUT ;
    USE SIGNAL ;
    PORT
      LAYER M4 ;
        RECT 576.8500 1639.4800 576.9500 1640.0000 ;
    END
  END out0[139]
  PIN out0[138]
    DIRECTION OUTPUT ;
    USE SIGNAL ;
    PORT
      LAYER M4 ;
        RECT 582.8500 1639.4800 582.9500 1640.0000 ;
    END
  END out0[138]
  PIN out0[137]
    DIRECTION OUTPUT ;
    USE SIGNAL ;
    PORT
      LAYER M4 ;
        RECT 588.8500 1639.4800 588.9500 1640.0000 ;
    END
  END out0[137]
  PIN out0[136]
    DIRECTION OUTPUT ;
    USE SIGNAL ;
    PORT
      LAYER M4 ;
        RECT 594.8500 1639.4800 594.9500 1640.0000 ;
    END
  END out0[136]
  PIN out0[135]
    DIRECTION OUTPUT ;
    USE SIGNAL ;
    PORT
      LAYER M4 ;
        RECT 600.8500 1639.4800 600.9500 1640.0000 ;
    END
  END out0[135]
  PIN out0[134]
    DIRECTION OUTPUT ;
    USE SIGNAL ;
    PORT
      LAYER M4 ;
        RECT 606.8500 1639.4800 606.9500 1640.0000 ;
    END
  END out0[134]
  PIN out0[133]
    DIRECTION OUTPUT ;
    USE SIGNAL ;
    PORT
      LAYER M4 ;
        RECT 612.8500 1639.4800 612.9500 1640.0000 ;
    END
  END out0[133]
  PIN out0[132]
    DIRECTION OUTPUT ;
    USE SIGNAL ;
    PORT
      LAYER M4 ;
        RECT 618.8500 1639.4800 618.9500 1640.0000 ;
    END
  END out0[132]
  PIN out0[131]
    DIRECTION OUTPUT ;
    USE SIGNAL ;
    PORT
      LAYER M4 ;
        RECT 624.8500 1639.4800 624.9500 1640.0000 ;
    END
  END out0[131]
  PIN out0[130]
    DIRECTION OUTPUT ;
    USE SIGNAL ;
    PORT
      LAYER M4 ;
        RECT 630.8500 1639.4800 630.9500 1640.0000 ;
    END
  END out0[130]
  PIN out0[129]
    DIRECTION OUTPUT ;
    USE SIGNAL ;
    PORT
      LAYER M4 ;
        RECT 636.8500 1639.4800 636.9500 1640.0000 ;
    END
  END out0[129]
  PIN out0[128]
    DIRECTION OUTPUT ;
    USE SIGNAL ;
    PORT
      LAYER M4 ;
        RECT 642.8500 1639.4800 642.9500 1640.0000 ;
    END
  END out0[128]
  PIN out0[127]
    DIRECTION OUTPUT ;
    USE SIGNAL ;
    PORT
      LAYER M4 ;
        RECT 648.8500 1639.4800 648.9500 1640.0000 ;
    END
  END out0[127]
  PIN out0[126]
    DIRECTION OUTPUT ;
    USE SIGNAL ;
    PORT
      LAYER M4 ;
        RECT 654.8500 1639.4800 654.9500 1640.0000 ;
    END
  END out0[126]
  PIN out0[125]
    DIRECTION OUTPUT ;
    USE SIGNAL ;
    PORT
      LAYER M4 ;
        RECT 660.8500 1639.4800 660.9500 1640.0000 ;
    END
  END out0[125]
  PIN out0[124]
    DIRECTION OUTPUT ;
    USE SIGNAL ;
    PORT
      LAYER M4 ;
        RECT 666.8500 1639.4800 666.9500 1640.0000 ;
    END
  END out0[124]
  PIN out0[123]
    DIRECTION OUTPUT ;
    USE SIGNAL ;
    PORT
      LAYER M4 ;
        RECT 672.8500 1639.4800 672.9500 1640.0000 ;
    END
  END out0[123]
  PIN out0[122]
    DIRECTION OUTPUT ;
    USE SIGNAL ;
    PORT
      LAYER M4 ;
        RECT 678.8500 1639.4800 678.9500 1640.0000 ;
    END
  END out0[122]
  PIN out0[121]
    DIRECTION OUTPUT ;
    USE SIGNAL ;
    PORT
      LAYER M4 ;
        RECT 684.8500 1639.4800 684.9500 1640.0000 ;
    END
  END out0[121]
  PIN out0[120]
    DIRECTION OUTPUT ;
    USE SIGNAL ;
    PORT
      LAYER M4 ;
        RECT 690.8500 1639.4800 690.9500 1640.0000 ;
    END
  END out0[120]
  PIN out0[119]
    DIRECTION OUTPUT ;
    USE SIGNAL ;
    PORT
      LAYER M4 ;
        RECT 696.8500 1639.4800 696.9500 1640.0000 ;
    END
  END out0[119]
  PIN out0[118]
    DIRECTION OUTPUT ;
    USE SIGNAL ;
    PORT
      LAYER M4 ;
        RECT 702.8500 1639.4800 702.9500 1640.0000 ;
    END
  END out0[118]
  PIN out0[117]
    DIRECTION OUTPUT ;
    USE SIGNAL ;
    PORT
      LAYER M4 ;
        RECT 708.8500 1639.4800 708.9500 1640.0000 ;
    END
  END out0[117]
  PIN out0[116]
    DIRECTION OUTPUT ;
    USE SIGNAL ;
    PORT
      LAYER M4 ;
        RECT 714.8500 1639.4800 714.9500 1640.0000 ;
    END
  END out0[116]
  PIN out0[115]
    DIRECTION OUTPUT ;
    USE SIGNAL ;
    PORT
      LAYER M4 ;
        RECT 720.8500 1639.4800 720.9500 1640.0000 ;
    END
  END out0[115]
  PIN out0[114]
    DIRECTION OUTPUT ;
    USE SIGNAL ;
    PORT
      LAYER M4 ;
        RECT 726.8500 1639.4800 726.9500 1640.0000 ;
    END
  END out0[114]
  PIN out0[113]
    DIRECTION OUTPUT ;
    USE SIGNAL ;
    PORT
      LAYER M4 ;
        RECT 732.8500 1639.4800 732.9500 1640.0000 ;
    END
  END out0[113]
  PIN out0[112]
    DIRECTION OUTPUT ;
    USE SIGNAL ;
    PORT
      LAYER M4 ;
        RECT 738.8500 1639.4800 738.9500 1640.0000 ;
    END
  END out0[112]
  PIN out0[111]
    DIRECTION OUTPUT ;
    USE SIGNAL ;
    PORT
      LAYER M4 ;
        RECT 744.8500 1639.4800 744.9500 1640.0000 ;
    END
  END out0[111]
  PIN out0[110]
    DIRECTION OUTPUT ;
    USE SIGNAL ;
    PORT
      LAYER M4 ;
        RECT 750.8500 1639.4800 750.9500 1640.0000 ;
    END
  END out0[110]
  PIN out0[109]
    DIRECTION OUTPUT ;
    USE SIGNAL ;
    PORT
      LAYER M4 ;
        RECT 756.8500 1639.4800 756.9500 1640.0000 ;
    END
  END out0[109]
  PIN out0[108]
    DIRECTION OUTPUT ;
    USE SIGNAL ;
    PORT
      LAYER M4 ;
        RECT 762.8500 1639.4800 762.9500 1640.0000 ;
    END
  END out0[108]
  PIN out0[107]
    DIRECTION OUTPUT ;
    USE SIGNAL ;
    PORT
      LAYER M4 ;
        RECT 768.8500 1639.4800 768.9500 1640.0000 ;
    END
  END out0[107]
  PIN out0[106]
    DIRECTION OUTPUT ;
    USE SIGNAL ;
    PORT
      LAYER M4 ;
        RECT 774.8500 1639.4800 774.9500 1640.0000 ;
    END
  END out0[106]
  PIN out0[105]
    DIRECTION OUTPUT ;
    USE SIGNAL ;
    PORT
      LAYER M4 ;
        RECT 780.8500 1639.4800 780.9500 1640.0000 ;
    END
  END out0[105]
  PIN out0[104]
    DIRECTION OUTPUT ;
    USE SIGNAL ;
    PORT
      LAYER M4 ;
        RECT 786.8500 1639.4800 786.9500 1640.0000 ;
    END
  END out0[104]
  PIN out0[103]
    DIRECTION OUTPUT ;
    USE SIGNAL ;
    PORT
      LAYER M4 ;
        RECT 792.8500 1639.4800 792.9500 1640.0000 ;
    END
  END out0[103]
  PIN out0[102]
    DIRECTION OUTPUT ;
    USE SIGNAL ;
    PORT
      LAYER M4 ;
        RECT 798.8500 1639.4800 798.9500 1640.0000 ;
    END
  END out0[102]
  PIN out0[101]
    DIRECTION OUTPUT ;
    USE SIGNAL ;
    PORT
      LAYER M4 ;
        RECT 804.8500 1639.4800 804.9500 1640.0000 ;
    END
  END out0[101]
  PIN out0[100]
    DIRECTION OUTPUT ;
    USE SIGNAL ;
    PORT
      LAYER M4 ;
        RECT 810.8500 1639.4800 810.9500 1640.0000 ;
    END
  END out0[100]
  PIN out0[99]
    DIRECTION OUTPUT ;
    USE SIGNAL ;
    PORT
      LAYER M4 ;
        RECT 816.8500 1639.4800 816.9500 1640.0000 ;
    END
  END out0[99]
  PIN out0[98]
    DIRECTION OUTPUT ;
    USE SIGNAL ;
    PORT
      LAYER M4 ;
        RECT 822.8500 1639.4800 822.9500 1640.0000 ;
    END
  END out0[98]
  PIN out0[97]
    DIRECTION OUTPUT ;
    USE SIGNAL ;
    PORT
      LAYER M4 ;
        RECT 828.8500 1639.4800 828.9500 1640.0000 ;
    END
  END out0[97]
  PIN out0[96]
    DIRECTION OUTPUT ;
    USE SIGNAL ;
    PORT
      LAYER M4 ;
        RECT 834.8500 1639.4800 834.9500 1640.0000 ;
    END
  END out0[96]
  PIN out0[95]
    DIRECTION OUTPUT ;
    USE SIGNAL ;
    PORT
      LAYER M4 ;
        RECT 840.8500 1639.4800 840.9500 1640.0000 ;
    END
  END out0[95]
  PIN out0[94]
    DIRECTION OUTPUT ;
    USE SIGNAL ;
    PORT
      LAYER M4 ;
        RECT 846.8500 1639.4800 846.9500 1640.0000 ;
    END
  END out0[94]
  PIN out0[93]
    DIRECTION OUTPUT ;
    USE SIGNAL ;
    PORT
      LAYER M4 ;
        RECT 852.8500 1639.4800 852.9500 1640.0000 ;
    END
  END out0[93]
  PIN out0[92]
    DIRECTION OUTPUT ;
    USE SIGNAL ;
    PORT
      LAYER M4 ;
        RECT 858.8500 1639.4800 858.9500 1640.0000 ;
    END
  END out0[92]
  PIN out0[91]
    DIRECTION OUTPUT ;
    USE SIGNAL ;
    PORT
      LAYER M4 ;
        RECT 864.8500 1639.4800 864.9500 1640.0000 ;
    END
  END out0[91]
  PIN out0[90]
    DIRECTION OUTPUT ;
    USE SIGNAL ;
    PORT
      LAYER M4 ;
        RECT 870.8500 1639.4800 870.9500 1640.0000 ;
    END
  END out0[90]
  PIN out0[89]
    DIRECTION OUTPUT ;
    USE SIGNAL ;
    PORT
      LAYER M4 ;
        RECT 876.8500 1639.4800 876.9500 1640.0000 ;
    END
  END out0[89]
  PIN out0[88]
    DIRECTION OUTPUT ;
    USE SIGNAL ;
    PORT
      LAYER M4 ;
        RECT 882.8500 1639.4800 882.9500 1640.0000 ;
    END
  END out0[88]
  PIN out0[87]
    DIRECTION OUTPUT ;
    USE SIGNAL ;
    PORT
      LAYER M4 ;
        RECT 888.8500 1639.4800 888.9500 1640.0000 ;
    END
  END out0[87]
  PIN out0[86]
    DIRECTION OUTPUT ;
    USE SIGNAL ;
    PORT
      LAYER M4 ;
        RECT 894.8500 1639.4800 894.9500 1640.0000 ;
    END
  END out0[86]
  PIN out0[85]
    DIRECTION OUTPUT ;
    USE SIGNAL ;
    PORT
      LAYER M4 ;
        RECT 900.8500 1639.4800 900.9500 1640.0000 ;
    END
  END out0[85]
  PIN out0[84]
    DIRECTION OUTPUT ;
    USE SIGNAL ;
    PORT
      LAYER M4 ;
        RECT 906.8500 1639.4800 906.9500 1640.0000 ;
    END
  END out0[84]
  PIN out0[83]
    DIRECTION OUTPUT ;
    USE SIGNAL ;
    PORT
      LAYER M4 ;
        RECT 912.8500 1639.4800 912.9500 1640.0000 ;
    END
  END out0[83]
  PIN out0[82]
    DIRECTION OUTPUT ;
    USE SIGNAL ;
    PORT
      LAYER M4 ;
        RECT 918.8500 1639.4800 918.9500 1640.0000 ;
    END
  END out0[82]
  PIN out0[81]
    DIRECTION OUTPUT ;
    USE SIGNAL ;
    PORT
      LAYER M4 ;
        RECT 924.8500 1639.4800 924.9500 1640.0000 ;
    END
  END out0[81]
  PIN out0[80]
    DIRECTION OUTPUT ;
    USE SIGNAL ;
    PORT
      LAYER M4 ;
        RECT 930.8500 1639.4800 930.9500 1640.0000 ;
    END
  END out0[80]
  PIN out0[79]
    DIRECTION OUTPUT ;
    USE SIGNAL ;
    PORT
      LAYER M4 ;
        RECT 936.8500 1639.4800 936.9500 1640.0000 ;
    END
  END out0[79]
  PIN out0[78]
    DIRECTION OUTPUT ;
    USE SIGNAL ;
    PORT
      LAYER M4 ;
        RECT 942.8500 1639.4800 942.9500 1640.0000 ;
    END
  END out0[78]
  PIN out0[77]
    DIRECTION OUTPUT ;
    USE SIGNAL ;
    PORT
      LAYER M4 ;
        RECT 948.8500 1639.4800 948.9500 1640.0000 ;
    END
  END out0[77]
  PIN out0[76]
    DIRECTION OUTPUT ;
    USE SIGNAL ;
    PORT
      LAYER M4 ;
        RECT 954.8500 1639.4800 954.9500 1640.0000 ;
    END
  END out0[76]
  PIN out0[75]
    DIRECTION OUTPUT ;
    USE SIGNAL ;
    PORT
      LAYER M4 ;
        RECT 960.8500 1639.4800 960.9500 1640.0000 ;
    END
  END out0[75]
  PIN out0[74]
    DIRECTION OUTPUT ;
    USE SIGNAL ;
    PORT
      LAYER M4 ;
        RECT 966.8500 1639.4800 966.9500 1640.0000 ;
    END
  END out0[74]
  PIN out0[73]
    DIRECTION OUTPUT ;
    USE SIGNAL ;
    PORT
      LAYER M4 ;
        RECT 972.8500 1639.4800 972.9500 1640.0000 ;
    END
  END out0[73]
  PIN out0[72]
    DIRECTION OUTPUT ;
    USE SIGNAL ;
    PORT
      LAYER M4 ;
        RECT 978.8500 1639.4800 978.9500 1640.0000 ;
    END
  END out0[72]
  PIN out0[71]
    DIRECTION OUTPUT ;
    USE SIGNAL ;
    PORT
      LAYER M4 ;
        RECT 984.8500 1639.4800 984.9500 1640.0000 ;
    END
  END out0[71]
  PIN out0[70]
    DIRECTION OUTPUT ;
    USE SIGNAL ;
    PORT
      LAYER M4 ;
        RECT 990.8500 1639.4800 990.9500 1640.0000 ;
    END
  END out0[70]
  PIN out0[69]
    DIRECTION OUTPUT ;
    USE SIGNAL ;
    PORT
      LAYER M4 ;
        RECT 996.8500 1639.4800 996.9500 1640.0000 ;
    END
  END out0[69]
  PIN out0[68]
    DIRECTION OUTPUT ;
    USE SIGNAL ;
    PORT
      LAYER M4 ;
        RECT 1002.8500 1639.4800 1002.9500 1640.0000 ;
    END
  END out0[68]
  PIN out0[67]
    DIRECTION OUTPUT ;
    USE SIGNAL ;
    PORT
      LAYER M4 ;
        RECT 1008.8500 1639.4800 1008.9500 1640.0000 ;
    END
  END out0[67]
  PIN out0[66]
    DIRECTION OUTPUT ;
    USE SIGNAL ;
    PORT
      LAYER M4 ;
        RECT 1014.8500 1639.4800 1014.9500 1640.0000 ;
    END
  END out0[66]
  PIN out0[65]
    DIRECTION OUTPUT ;
    USE SIGNAL ;
    PORT
      LAYER M4 ;
        RECT 1020.8500 1639.4800 1020.9500 1640.0000 ;
    END
  END out0[65]
  PIN out0[64]
    DIRECTION OUTPUT ;
    USE SIGNAL ;
    PORT
      LAYER M4 ;
        RECT 1026.8500 1639.4800 1026.9500 1640.0000 ;
    END
  END out0[64]
  PIN out0[63]
    DIRECTION OUTPUT ;
    USE SIGNAL ;
    PORT
      LAYER M4 ;
        RECT 1032.8500 1639.4800 1032.9500 1640.0000 ;
    END
  END out0[63]
  PIN out0[62]
    DIRECTION OUTPUT ;
    USE SIGNAL ;
    PORT
      LAYER M4 ;
        RECT 1038.8500 1639.4800 1038.9500 1640.0000 ;
    END
  END out0[62]
  PIN out0[61]
    DIRECTION OUTPUT ;
    USE SIGNAL ;
    PORT
      LAYER M4 ;
        RECT 1044.8500 1639.4800 1044.9500 1640.0000 ;
    END
  END out0[61]
  PIN out0[60]
    DIRECTION OUTPUT ;
    USE SIGNAL ;
    PORT
      LAYER M4 ;
        RECT 1050.8500 1639.4800 1050.9500 1640.0000 ;
    END
  END out0[60]
  PIN out0[59]
    DIRECTION OUTPUT ;
    USE SIGNAL ;
    PORT
      LAYER M4 ;
        RECT 1056.8500 1639.4800 1056.9500 1640.0000 ;
    END
  END out0[59]
  PIN out0[58]
    DIRECTION OUTPUT ;
    USE SIGNAL ;
    PORT
      LAYER M4 ;
        RECT 1062.8500 1639.4800 1062.9500 1640.0000 ;
    END
  END out0[58]
  PIN out0[57]
    DIRECTION OUTPUT ;
    USE SIGNAL ;
    PORT
      LAYER M4 ;
        RECT 1068.8500 1639.4800 1068.9500 1640.0000 ;
    END
  END out0[57]
  PIN out0[56]
    DIRECTION OUTPUT ;
    USE SIGNAL ;
    PORT
      LAYER M4 ;
        RECT 1074.8500 1639.4800 1074.9500 1640.0000 ;
    END
  END out0[56]
  PIN out0[55]
    DIRECTION OUTPUT ;
    USE SIGNAL ;
    PORT
      LAYER M4 ;
        RECT 1080.8500 1639.4800 1080.9500 1640.0000 ;
    END
  END out0[55]
  PIN out0[54]
    DIRECTION OUTPUT ;
    USE SIGNAL ;
    PORT
      LAYER M4 ;
        RECT 1086.8500 1639.4800 1086.9500 1640.0000 ;
    END
  END out0[54]
  PIN out0[53]
    DIRECTION OUTPUT ;
    USE SIGNAL ;
    PORT
      LAYER M4 ;
        RECT 1092.8500 1639.4800 1092.9500 1640.0000 ;
    END
  END out0[53]
  PIN out0[52]
    DIRECTION OUTPUT ;
    USE SIGNAL ;
    PORT
      LAYER M4 ;
        RECT 1098.8500 1639.4800 1098.9500 1640.0000 ;
    END
  END out0[52]
  PIN out0[51]
    DIRECTION OUTPUT ;
    USE SIGNAL ;
    PORT
      LAYER M4 ;
        RECT 1104.8500 1639.4800 1104.9500 1640.0000 ;
    END
  END out0[51]
  PIN out0[50]
    DIRECTION OUTPUT ;
    USE SIGNAL ;
    PORT
      LAYER M4 ;
        RECT 1110.8500 1639.4800 1110.9500 1640.0000 ;
    END
  END out0[50]
  PIN out0[49]
    DIRECTION OUTPUT ;
    USE SIGNAL ;
    PORT
      LAYER M4 ;
        RECT 1116.8500 1639.4800 1116.9500 1640.0000 ;
    END
  END out0[49]
  PIN out0[48]
    DIRECTION OUTPUT ;
    USE SIGNAL ;
    PORT
      LAYER M4 ;
        RECT 1122.8500 1639.4800 1122.9500 1640.0000 ;
    END
  END out0[48]
  PIN out0[47]
    DIRECTION OUTPUT ;
    USE SIGNAL ;
    PORT
      LAYER M4 ;
        RECT 1128.8500 1639.4800 1128.9500 1640.0000 ;
    END
  END out0[47]
  PIN out0[46]
    DIRECTION OUTPUT ;
    USE SIGNAL ;
    PORT
      LAYER M4 ;
        RECT 1134.8500 1639.4800 1134.9500 1640.0000 ;
    END
  END out0[46]
  PIN out0[45]
    DIRECTION OUTPUT ;
    USE SIGNAL ;
    PORT
      LAYER M4 ;
        RECT 1140.8500 1639.4800 1140.9500 1640.0000 ;
    END
  END out0[45]
  PIN out0[44]
    DIRECTION OUTPUT ;
    USE SIGNAL ;
    PORT
      LAYER M4 ;
        RECT 1146.8500 1639.4800 1146.9500 1640.0000 ;
    END
  END out0[44]
  PIN out0[43]
    DIRECTION OUTPUT ;
    USE SIGNAL ;
    PORT
      LAYER M4 ;
        RECT 1152.8500 1639.4800 1152.9500 1640.0000 ;
    END
  END out0[43]
  PIN out0[42]
    DIRECTION OUTPUT ;
    USE SIGNAL ;
    PORT
      LAYER M4 ;
        RECT 1158.8500 1639.4800 1158.9500 1640.0000 ;
    END
  END out0[42]
  PIN out0[41]
    DIRECTION OUTPUT ;
    USE SIGNAL ;
    PORT
      LAYER M4 ;
        RECT 1164.8500 1639.4800 1164.9500 1640.0000 ;
    END
  END out0[41]
  PIN out0[40]
    DIRECTION OUTPUT ;
    USE SIGNAL ;
    PORT
      LAYER M4 ;
        RECT 1170.8500 1639.4800 1170.9500 1640.0000 ;
    END
  END out0[40]
  PIN out0[39]
    DIRECTION OUTPUT ;
    USE SIGNAL ;
    PORT
      LAYER M4 ;
        RECT 1176.8500 1639.4800 1176.9500 1640.0000 ;
    END
  END out0[39]
  PIN out0[38]
    DIRECTION OUTPUT ;
    USE SIGNAL ;
    PORT
      LAYER M4 ;
        RECT 1182.8500 1639.4800 1182.9500 1640.0000 ;
    END
  END out0[38]
  PIN out0[37]
    DIRECTION OUTPUT ;
    USE SIGNAL ;
    PORT
      LAYER M4 ;
        RECT 1188.8500 1639.4800 1188.9500 1640.0000 ;
    END
  END out0[37]
  PIN out0[36]
    DIRECTION OUTPUT ;
    USE SIGNAL ;
    PORT
      LAYER M4 ;
        RECT 1194.8500 1639.4800 1194.9500 1640.0000 ;
    END
  END out0[36]
  PIN out0[35]
    DIRECTION OUTPUT ;
    USE SIGNAL ;
    PORT
      LAYER M4 ;
        RECT 1200.8500 1639.4800 1200.9500 1640.0000 ;
    END
  END out0[35]
  PIN out0[34]
    DIRECTION OUTPUT ;
    USE SIGNAL ;
    PORT
      LAYER M4 ;
        RECT 1206.8500 1639.4800 1206.9500 1640.0000 ;
    END
  END out0[34]
  PIN out0[33]
    DIRECTION OUTPUT ;
    USE SIGNAL ;
    PORT
      LAYER M4 ;
        RECT 1212.8500 1639.4800 1212.9500 1640.0000 ;
    END
  END out0[33]
  PIN out0[32]
    DIRECTION OUTPUT ;
    USE SIGNAL ;
    PORT
      LAYER M4 ;
        RECT 1218.8500 1639.4800 1218.9500 1640.0000 ;
    END
  END out0[32]
  PIN out0[31]
    DIRECTION OUTPUT ;
    USE SIGNAL ;
    PORT
      LAYER M4 ;
        RECT 1224.8500 1639.4800 1224.9500 1640.0000 ;
    END
  END out0[31]
  PIN out0[30]
    DIRECTION OUTPUT ;
    USE SIGNAL ;
    PORT
      LAYER M4 ;
        RECT 1230.8500 1639.4800 1230.9500 1640.0000 ;
    END
  END out0[30]
  PIN out0[29]
    DIRECTION OUTPUT ;
    USE SIGNAL ;
    PORT
      LAYER M4 ;
        RECT 1236.8500 1639.4800 1236.9500 1640.0000 ;
    END
  END out0[29]
  PIN out0[28]
    DIRECTION OUTPUT ;
    USE SIGNAL ;
    PORT
      LAYER M4 ;
        RECT 1242.8500 1639.4800 1242.9500 1640.0000 ;
    END
  END out0[28]
  PIN out0[27]
    DIRECTION OUTPUT ;
    USE SIGNAL ;
    PORT
      LAYER M4 ;
        RECT 1248.8500 1639.4800 1248.9500 1640.0000 ;
    END
  END out0[27]
  PIN out0[26]
    DIRECTION OUTPUT ;
    USE SIGNAL ;
    PORT
      LAYER M4 ;
        RECT 1254.8500 1639.4800 1254.9500 1640.0000 ;
    END
  END out0[26]
  PIN out0[25]
    DIRECTION OUTPUT ;
    USE SIGNAL ;
    PORT
      LAYER M4 ;
        RECT 1260.8500 1639.4800 1260.9500 1640.0000 ;
    END
  END out0[25]
  PIN out0[24]
    DIRECTION OUTPUT ;
    USE SIGNAL ;
    PORT
      LAYER M4 ;
        RECT 1266.8500 1639.4800 1266.9500 1640.0000 ;
    END
  END out0[24]
  PIN out0[23]
    DIRECTION OUTPUT ;
    USE SIGNAL ;
    PORT
      LAYER M4 ;
        RECT 1272.8500 1639.4800 1272.9500 1640.0000 ;
    END
  END out0[23]
  PIN out0[22]
    DIRECTION OUTPUT ;
    USE SIGNAL ;
    PORT
      LAYER M4 ;
        RECT 1278.8500 1639.4800 1278.9500 1640.0000 ;
    END
  END out0[22]
  PIN out0[21]
    DIRECTION OUTPUT ;
    USE SIGNAL ;
    PORT
      LAYER M4 ;
        RECT 1284.8500 1639.4800 1284.9500 1640.0000 ;
    END
  END out0[21]
  PIN out0[20]
    DIRECTION OUTPUT ;
    USE SIGNAL ;
    PORT
      LAYER M4 ;
        RECT 1290.8500 1639.4800 1290.9500 1640.0000 ;
    END
  END out0[20]
  PIN out0[19]
    DIRECTION OUTPUT ;
    USE SIGNAL ;
    PORT
      LAYER M4 ;
        RECT 1296.8500 1639.4800 1296.9500 1640.0000 ;
    END
  END out0[19]
  PIN out0[18]
    DIRECTION OUTPUT ;
    USE SIGNAL ;
    PORT
      LAYER M4 ;
        RECT 1302.8500 1639.4800 1302.9500 1640.0000 ;
    END
  END out0[18]
  PIN out0[17]
    DIRECTION OUTPUT ;
    USE SIGNAL ;
    PORT
      LAYER M4 ;
        RECT 1308.8500 1639.4800 1308.9500 1640.0000 ;
    END
  END out0[17]
  PIN out0[16]
    DIRECTION OUTPUT ;
    USE SIGNAL ;
    PORT
      LAYER M4 ;
        RECT 1314.8500 1639.4800 1314.9500 1640.0000 ;
    END
  END out0[16]
  PIN out0[15]
    DIRECTION OUTPUT ;
    USE SIGNAL ;
    PORT
      LAYER M4 ;
        RECT 1320.8500 1639.4800 1320.9500 1640.0000 ;
    END
  END out0[15]
  PIN out0[14]
    DIRECTION OUTPUT ;
    USE SIGNAL ;
    PORT
      LAYER M4 ;
        RECT 1326.8500 1639.4800 1326.9500 1640.0000 ;
    END
  END out0[14]
  PIN out0[13]
    DIRECTION OUTPUT ;
    USE SIGNAL ;
    PORT
      LAYER M4 ;
        RECT 1332.8500 1639.4800 1332.9500 1640.0000 ;
    END
  END out0[13]
  PIN out0[12]
    DIRECTION OUTPUT ;
    USE SIGNAL ;
    PORT
      LAYER M4 ;
        RECT 1338.8500 1639.4800 1338.9500 1640.0000 ;
    END
  END out0[12]
  PIN out0[11]
    DIRECTION OUTPUT ;
    USE SIGNAL ;
    PORT
      LAYER M4 ;
        RECT 1344.8500 1639.4800 1344.9500 1640.0000 ;
    END
  END out0[11]
  PIN out0[10]
    DIRECTION OUTPUT ;
    USE SIGNAL ;
    PORT
      LAYER M4 ;
        RECT 1350.8500 1639.4800 1350.9500 1640.0000 ;
    END
  END out0[10]
  PIN out0[9]
    DIRECTION OUTPUT ;
    USE SIGNAL ;
    PORT
      LAYER M4 ;
        RECT 1356.8500 1639.4800 1356.9500 1640.0000 ;
    END
  END out0[9]
  PIN out0[8]
    DIRECTION OUTPUT ;
    USE SIGNAL ;
    PORT
      LAYER M4 ;
        RECT 1362.8500 1639.4800 1362.9500 1640.0000 ;
    END
  END out0[8]
  PIN out0[7]
    DIRECTION OUTPUT ;
    USE SIGNAL ;
    PORT
      LAYER M4 ;
        RECT 1368.8500 1639.4800 1368.9500 1640.0000 ;
    END
  END out0[7]
  PIN out0[6]
    DIRECTION OUTPUT ;
    USE SIGNAL ;
    PORT
      LAYER M4 ;
        RECT 1374.8500 1639.4800 1374.9500 1640.0000 ;
    END
  END out0[6]
  PIN out0[5]
    DIRECTION OUTPUT ;
    USE SIGNAL ;
    PORT
      LAYER M4 ;
        RECT 1380.8500 1639.4800 1380.9500 1640.0000 ;
    END
  END out0[5]
  PIN out0[4]
    DIRECTION OUTPUT ;
    USE SIGNAL ;
    PORT
      LAYER M4 ;
        RECT 1386.8500 1639.4800 1386.9500 1640.0000 ;
    END
  END out0[4]
  PIN out0[3]
    DIRECTION OUTPUT ;
    USE SIGNAL ;
    PORT
      LAYER M4 ;
        RECT 1392.8500 1639.4800 1392.9500 1640.0000 ;
    END
  END out0[3]
  PIN out0[2]
    DIRECTION OUTPUT ;
    USE SIGNAL ;
    PORT
      LAYER M4 ;
        RECT 1398.8500 1639.4800 1398.9500 1640.0000 ;
    END
  END out0[2]
  PIN out0[1]
    DIRECTION OUTPUT ;
    USE SIGNAL ;
    PORT
      LAYER M4 ;
        RECT 1404.8500 1639.4800 1404.9500 1640.0000 ;
    END
  END out0[1]
  PIN out0[0]
    DIRECTION OUTPUT ;
    USE SIGNAL ;
    PORT
      LAYER M4 ;
        RECT 1410.8500 1639.4800 1410.9500 1640.0000 ;
    END
  END out0[0]
  PIN out1[159]
    DIRECTION OUTPUT ;
    USE SIGNAL ;
    PORT
      LAYER M4 ;
        RECT 1416.8500 1639.4800 1416.9500 1640.0000 ;
    END
  END out1[159]
  PIN out1[158]
    DIRECTION OUTPUT ;
    USE SIGNAL ;
    PORT
      LAYER M4 ;
        RECT 1422.8500 1639.4800 1422.9500 1640.0000 ;
    END
  END out1[158]
  PIN out1[157]
    DIRECTION OUTPUT ;
    USE SIGNAL ;
    PORT
      LAYER M4 ;
        RECT 1428.8500 1639.4800 1428.9500 1640.0000 ;
    END
  END out1[157]
  PIN out1[156]
    DIRECTION OUTPUT ;
    USE SIGNAL ;
    PORT
      LAYER M4 ;
        RECT 1434.8500 1639.4800 1434.9500 1640.0000 ;
    END
  END out1[156]
  PIN out1[155]
    DIRECTION OUTPUT ;
    USE SIGNAL ;
    PORT
      LAYER M4 ;
        RECT 1440.8500 1639.4800 1440.9500 1640.0000 ;
    END
  END out1[155]
  PIN out1[154]
    DIRECTION OUTPUT ;
    USE SIGNAL ;
    PORT
      LAYER M4 ;
        RECT 1446.8500 1639.4800 1446.9500 1640.0000 ;
    END
  END out1[154]
  PIN out1[153]
    DIRECTION OUTPUT ;
    USE SIGNAL ;
    PORT
      LAYER M4 ;
        RECT 1452.8500 1639.4800 1452.9500 1640.0000 ;
    END
  END out1[153]
  PIN out1[152]
    DIRECTION OUTPUT ;
    USE SIGNAL ;
    PORT
      LAYER M4 ;
        RECT 1458.8500 1639.4800 1458.9500 1640.0000 ;
    END
  END out1[152]
  PIN out1[151]
    DIRECTION OUTPUT ;
    USE SIGNAL ;
    PORT
      LAYER M4 ;
        RECT 1464.8500 1639.4800 1464.9500 1640.0000 ;
    END
  END out1[151]
  PIN out1[150]
    DIRECTION OUTPUT ;
    USE SIGNAL ;
    PORT
      LAYER M4 ;
        RECT 1470.8500 1639.4800 1470.9500 1640.0000 ;
    END
  END out1[150]
  PIN out1[149]
    DIRECTION OUTPUT ;
    USE SIGNAL ;
    PORT
      LAYER M4 ;
        RECT 1476.8500 1639.4800 1476.9500 1640.0000 ;
    END
  END out1[149]
  PIN out1[148]
    DIRECTION OUTPUT ;
    USE SIGNAL ;
    PORT
      LAYER M4 ;
        RECT 1482.8500 1639.4800 1482.9500 1640.0000 ;
    END
  END out1[148]
  PIN out1[147]
    DIRECTION OUTPUT ;
    USE SIGNAL ;
    PORT
      LAYER M4 ;
        RECT 1488.8500 1639.4800 1488.9500 1640.0000 ;
    END
  END out1[147]
  PIN out1[146]
    DIRECTION OUTPUT ;
    USE SIGNAL ;
    PORT
      LAYER M4 ;
        RECT 1494.8500 1639.4800 1494.9500 1640.0000 ;
    END
  END out1[146]
  PIN out1[145]
    DIRECTION OUTPUT ;
    USE SIGNAL ;
    PORT
      LAYER M4 ;
        RECT 1500.8500 1639.4800 1500.9500 1640.0000 ;
    END
  END out1[145]
  PIN out1[144]
    DIRECTION OUTPUT ;
    USE SIGNAL ;
    PORT
      LAYER M4 ;
        RECT 1506.8500 1639.4800 1506.9500 1640.0000 ;
    END
  END out1[144]
  PIN out1[143]
    DIRECTION OUTPUT ;
    USE SIGNAL ;
    PORT
      LAYER M4 ;
        RECT 1512.8500 1639.4800 1512.9500 1640.0000 ;
    END
  END out1[143]
  PIN out1[142]
    DIRECTION OUTPUT ;
    USE SIGNAL ;
    PORT
      LAYER M4 ;
        RECT 1518.8500 1639.4800 1518.9500 1640.0000 ;
    END
  END out1[142]
  PIN out1[141]
    DIRECTION OUTPUT ;
    USE SIGNAL ;
    PORT
      LAYER M4 ;
        RECT 1524.8500 1639.4800 1524.9500 1640.0000 ;
    END
  END out1[141]
  PIN out1[140]
    DIRECTION OUTPUT ;
    USE SIGNAL ;
    PORT
      LAYER M4 ;
        RECT 1530.8500 1639.4800 1530.9500 1640.0000 ;
    END
  END out1[140]
  PIN out1[139]
    DIRECTION OUTPUT ;
    USE SIGNAL ;
    PORT
      LAYER M4 ;
        RECT 1536.8500 1639.4800 1536.9500 1640.0000 ;
    END
  END out1[139]
  PIN out1[138]
    DIRECTION OUTPUT ;
    USE SIGNAL ;
    PORT
      LAYER M4 ;
        RECT 1542.8500 1639.4800 1542.9500 1640.0000 ;
    END
  END out1[138]
  PIN out1[137]
    DIRECTION OUTPUT ;
    USE SIGNAL ;
    PORT
      LAYER M4 ;
        RECT 1548.8500 1639.4800 1548.9500 1640.0000 ;
    END
  END out1[137]
  PIN out1[136]
    DIRECTION OUTPUT ;
    USE SIGNAL ;
    PORT
      LAYER M4 ;
        RECT 1554.8500 1639.4800 1554.9500 1640.0000 ;
    END
  END out1[136]
  PIN out1[135]
    DIRECTION OUTPUT ;
    USE SIGNAL ;
    PORT
      LAYER M4 ;
        RECT 1560.8500 1639.4800 1560.9500 1640.0000 ;
    END
  END out1[135]
  PIN out1[134]
    DIRECTION OUTPUT ;
    USE SIGNAL ;
    PORT
      LAYER M4 ;
        RECT 1566.8500 1639.4800 1566.9500 1640.0000 ;
    END
  END out1[134]
  PIN out1[133]
    DIRECTION OUTPUT ;
    USE SIGNAL ;
    PORT
      LAYER M4 ;
        RECT 1572.8500 1639.4800 1572.9500 1640.0000 ;
    END
  END out1[133]
  PIN out1[132]
    DIRECTION OUTPUT ;
    USE SIGNAL ;
    PORT
      LAYER M4 ;
        RECT 1578.8500 1639.4800 1578.9500 1640.0000 ;
    END
  END out1[132]
  PIN out1[131]
    DIRECTION OUTPUT ;
    USE SIGNAL ;
    PORT
      LAYER M4 ;
        RECT 1584.8500 1639.4800 1584.9500 1640.0000 ;
    END
  END out1[131]
  PIN out1[130]
    DIRECTION OUTPUT ;
    USE SIGNAL ;
    PORT
      LAYER M4 ;
        RECT 1590.8500 1639.4800 1590.9500 1640.0000 ;
    END
  END out1[130]
  PIN out1[129]
    DIRECTION OUTPUT ;
    USE SIGNAL ;
    PORT
      LAYER M4 ;
        RECT 1596.8500 1639.4800 1596.9500 1640.0000 ;
    END
  END out1[129]
  PIN out1[128]
    DIRECTION OUTPUT ;
    USE SIGNAL ;
    PORT
      LAYER M4 ;
        RECT 1602.8500 1639.4800 1602.9500 1640.0000 ;
    END
  END out1[128]
  PIN out1[127]
    DIRECTION OUTPUT ;
    USE SIGNAL ;
    PORT
      LAYER M4 ;
        RECT 1608.8500 1639.4800 1608.9500 1640.0000 ;
    END
  END out1[127]
  PIN out1[126]
    DIRECTION OUTPUT ;
    USE SIGNAL ;
    PORT
      LAYER M4 ;
        RECT 1614.8500 1639.4800 1614.9500 1640.0000 ;
    END
  END out1[126]
  PIN out1[125]
    DIRECTION OUTPUT ;
    USE SIGNAL ;
    PORT
      LAYER M4 ;
        RECT 1620.8500 1639.4800 1620.9500 1640.0000 ;
    END
  END out1[125]
  PIN out1[124]
    DIRECTION OUTPUT ;
    USE SIGNAL ;
    PORT
      LAYER M4 ;
        RECT 1626.8500 1639.4800 1626.9500 1640.0000 ;
    END
  END out1[124]
  PIN out1[123]
    DIRECTION OUTPUT ;
    USE SIGNAL ;
    PORT
      LAYER M4 ;
        RECT 1632.8500 1639.4800 1632.9500 1640.0000 ;
    END
  END out1[123]
  PIN out1[122]
    DIRECTION OUTPUT ;
    USE SIGNAL ;
    PORT
      LAYER M4 ;
        RECT 1638.8500 1639.4800 1638.9500 1640.0000 ;
    END
  END out1[122]
  PIN out1[121]
    DIRECTION OUTPUT ;
    USE SIGNAL ;
    PORT
      LAYER M4 ;
        RECT 1644.8500 1639.4800 1644.9500 1640.0000 ;
    END
  END out1[121]
  PIN out1[120]
    DIRECTION OUTPUT ;
    USE SIGNAL ;
    PORT
      LAYER M4 ;
        RECT 1650.8500 1639.4800 1650.9500 1640.0000 ;
    END
  END out1[120]
  PIN out1[119]
    DIRECTION OUTPUT ;
    USE SIGNAL ;
    PORT
      LAYER M4 ;
        RECT 1656.8500 1639.4800 1656.9500 1640.0000 ;
    END
  END out1[119]
  PIN out1[118]
    DIRECTION OUTPUT ;
    USE SIGNAL ;
    PORT
      LAYER M4 ;
        RECT 1662.8500 1639.4800 1662.9500 1640.0000 ;
    END
  END out1[118]
  PIN out1[117]
    DIRECTION OUTPUT ;
    USE SIGNAL ;
    PORT
      LAYER M4 ;
        RECT 1668.8500 1639.4800 1668.9500 1640.0000 ;
    END
  END out1[117]
  PIN out1[116]
    DIRECTION OUTPUT ;
    USE SIGNAL ;
    PORT
      LAYER M4 ;
        RECT 1674.8500 1639.4800 1674.9500 1640.0000 ;
    END
  END out1[116]
  PIN out1[115]
    DIRECTION OUTPUT ;
    USE SIGNAL ;
    PORT
      LAYER M4 ;
        RECT 1680.8500 1639.4800 1680.9500 1640.0000 ;
    END
  END out1[115]
  PIN out1[114]
    DIRECTION OUTPUT ;
    USE SIGNAL ;
    PORT
      LAYER M4 ;
        RECT 1686.8500 1639.4800 1686.9500 1640.0000 ;
    END
  END out1[114]
  PIN out1[113]
    DIRECTION OUTPUT ;
    USE SIGNAL ;
    PORT
      LAYER M4 ;
        RECT 1692.8500 1639.4800 1692.9500 1640.0000 ;
    END
  END out1[113]
  PIN out1[112]
    DIRECTION OUTPUT ;
    USE SIGNAL ;
    PORT
      LAYER M4 ;
        RECT 1698.8500 1639.4800 1698.9500 1640.0000 ;
    END
  END out1[112]
  PIN out1[111]
    DIRECTION OUTPUT ;
    USE SIGNAL ;
    PORT
      LAYER M4 ;
        RECT 1704.8500 1639.4800 1704.9500 1640.0000 ;
    END
  END out1[111]
  PIN out1[110]
    DIRECTION OUTPUT ;
    USE SIGNAL ;
    PORT
      LAYER M4 ;
        RECT 1710.8500 1639.4800 1710.9500 1640.0000 ;
    END
  END out1[110]
  PIN out1[109]
    DIRECTION OUTPUT ;
    USE SIGNAL ;
    PORT
      LAYER M4 ;
        RECT 1716.8500 1639.4800 1716.9500 1640.0000 ;
    END
  END out1[109]
  PIN out1[108]
    DIRECTION OUTPUT ;
    USE SIGNAL ;
    PORT
      LAYER M4 ;
        RECT 1722.8500 1639.4800 1722.9500 1640.0000 ;
    END
  END out1[108]
  PIN out1[107]
    DIRECTION OUTPUT ;
    USE SIGNAL ;
    PORT
      LAYER M4 ;
        RECT 1728.8500 1639.4800 1728.9500 1640.0000 ;
    END
  END out1[107]
  PIN out1[106]
    DIRECTION OUTPUT ;
    USE SIGNAL ;
    PORT
      LAYER M4 ;
        RECT 1734.8500 1639.4800 1734.9500 1640.0000 ;
    END
  END out1[106]
  PIN out1[105]
    DIRECTION OUTPUT ;
    USE SIGNAL ;
    PORT
      LAYER M4 ;
        RECT 1740.8500 1639.4800 1740.9500 1640.0000 ;
    END
  END out1[105]
  PIN out1[104]
    DIRECTION OUTPUT ;
    USE SIGNAL ;
    PORT
      LAYER M4 ;
        RECT 1746.8500 1639.4800 1746.9500 1640.0000 ;
    END
  END out1[104]
  PIN out1[103]
    DIRECTION OUTPUT ;
    USE SIGNAL ;
    PORT
      LAYER M4 ;
        RECT 1752.8500 1639.4800 1752.9500 1640.0000 ;
    END
  END out1[103]
  PIN out1[102]
    DIRECTION OUTPUT ;
    USE SIGNAL ;
    PORT
      LAYER M4 ;
        RECT 1758.8500 1639.4800 1758.9500 1640.0000 ;
    END
  END out1[102]
  PIN out1[101]
    DIRECTION OUTPUT ;
    USE SIGNAL ;
    PORT
      LAYER M4 ;
        RECT 1764.8500 1639.4800 1764.9500 1640.0000 ;
    END
  END out1[101]
  PIN out1[100]
    DIRECTION OUTPUT ;
    USE SIGNAL ;
    PORT
      LAYER M4 ;
        RECT 1770.8500 1639.4800 1770.9500 1640.0000 ;
    END
  END out1[100]
  PIN out1[99]
    DIRECTION OUTPUT ;
    USE SIGNAL ;
    PORT
      LAYER M4 ;
        RECT 1776.8500 1639.4800 1776.9500 1640.0000 ;
    END
  END out1[99]
  PIN out1[98]
    DIRECTION OUTPUT ;
    USE SIGNAL ;
    PORT
      LAYER M4 ;
        RECT 1782.8500 1639.4800 1782.9500 1640.0000 ;
    END
  END out1[98]
  PIN out1[97]
    DIRECTION OUTPUT ;
    USE SIGNAL ;
    PORT
      LAYER M4 ;
        RECT 1788.8500 1639.4800 1788.9500 1640.0000 ;
    END
  END out1[97]
  PIN out1[96]
    DIRECTION OUTPUT ;
    USE SIGNAL ;
    PORT
      LAYER M4 ;
        RECT 1794.8500 1639.4800 1794.9500 1640.0000 ;
    END
  END out1[96]
  PIN out1[95]
    DIRECTION OUTPUT ;
    USE SIGNAL ;
    PORT
      LAYER M4 ;
        RECT 1800.8500 1639.4800 1800.9500 1640.0000 ;
    END
  END out1[95]
  PIN out1[94]
    DIRECTION OUTPUT ;
    USE SIGNAL ;
    PORT
      LAYER M4 ;
        RECT 1806.8500 1639.4800 1806.9500 1640.0000 ;
    END
  END out1[94]
  PIN out1[93]
    DIRECTION OUTPUT ;
    USE SIGNAL ;
    PORT
      LAYER M4 ;
        RECT 1812.8500 1639.4800 1812.9500 1640.0000 ;
    END
  END out1[93]
  PIN out1[92]
    DIRECTION OUTPUT ;
    USE SIGNAL ;
    PORT
      LAYER M4 ;
        RECT 1818.8500 1639.4800 1818.9500 1640.0000 ;
    END
  END out1[92]
  PIN out1[91]
    DIRECTION OUTPUT ;
    USE SIGNAL ;
    PORT
      LAYER M4 ;
        RECT 1824.8500 1639.4800 1824.9500 1640.0000 ;
    END
  END out1[91]
  PIN out1[90]
    DIRECTION OUTPUT ;
    USE SIGNAL ;
    PORT
      LAYER M4 ;
        RECT 1830.8500 1639.4800 1830.9500 1640.0000 ;
    END
  END out1[90]
  PIN out1[89]
    DIRECTION OUTPUT ;
    USE SIGNAL ;
    PORT
      LAYER M4 ;
        RECT 1836.8500 1639.4800 1836.9500 1640.0000 ;
    END
  END out1[89]
  PIN out1[88]
    DIRECTION OUTPUT ;
    USE SIGNAL ;
    PORT
      LAYER M4 ;
        RECT 1842.8500 1639.4800 1842.9500 1640.0000 ;
    END
  END out1[88]
  PIN out1[87]
    DIRECTION OUTPUT ;
    USE SIGNAL ;
    PORT
      LAYER M4 ;
        RECT 1848.8500 1639.4800 1848.9500 1640.0000 ;
    END
  END out1[87]
  PIN out1[86]
    DIRECTION OUTPUT ;
    USE SIGNAL ;
    PORT
      LAYER M4 ;
        RECT 1854.8500 1639.4800 1854.9500 1640.0000 ;
    END
  END out1[86]
  PIN out1[85]
    DIRECTION OUTPUT ;
    USE SIGNAL ;
    PORT
      LAYER M4 ;
        RECT 1860.8500 1639.4800 1860.9500 1640.0000 ;
    END
  END out1[85]
  PIN out1[84]
    DIRECTION OUTPUT ;
    USE SIGNAL ;
    PORT
      LAYER M4 ;
        RECT 1866.8500 1639.4800 1866.9500 1640.0000 ;
    END
  END out1[84]
  PIN out1[83]
    DIRECTION OUTPUT ;
    USE SIGNAL ;
    PORT
      LAYER M4 ;
        RECT 1872.8500 1639.4800 1872.9500 1640.0000 ;
    END
  END out1[83]
  PIN out1[82]
    DIRECTION OUTPUT ;
    USE SIGNAL ;
    PORT
      LAYER M4 ;
        RECT 1878.8500 1639.4800 1878.9500 1640.0000 ;
    END
  END out1[82]
  PIN out1[81]
    DIRECTION OUTPUT ;
    USE SIGNAL ;
    PORT
      LAYER M4 ;
        RECT 1884.8500 1639.4800 1884.9500 1640.0000 ;
    END
  END out1[81]
  PIN out1[80]
    DIRECTION OUTPUT ;
    USE SIGNAL ;
    PORT
      LAYER M4 ;
        RECT 1890.8500 1639.4800 1890.9500 1640.0000 ;
    END
  END out1[80]
  PIN out1[79]
    DIRECTION OUTPUT ;
    USE SIGNAL ;
    PORT
      LAYER M4 ;
        RECT 1896.8500 1639.4800 1896.9500 1640.0000 ;
    END
  END out1[79]
  PIN out1[78]
    DIRECTION OUTPUT ;
    USE SIGNAL ;
    PORT
      LAYER M4 ;
        RECT 1902.8500 1639.4800 1902.9500 1640.0000 ;
    END
  END out1[78]
  PIN out1[77]
    DIRECTION OUTPUT ;
    USE SIGNAL ;
    PORT
      LAYER M4 ;
        RECT 1908.8500 1639.4800 1908.9500 1640.0000 ;
    END
  END out1[77]
  PIN out1[76]
    DIRECTION OUTPUT ;
    USE SIGNAL ;
    PORT
      LAYER M4 ;
        RECT 1914.8500 1639.4800 1914.9500 1640.0000 ;
    END
  END out1[76]
  PIN out1[75]
    DIRECTION OUTPUT ;
    USE SIGNAL ;
    PORT
      LAYER M4 ;
        RECT 1920.8500 1639.4800 1920.9500 1640.0000 ;
    END
  END out1[75]
  PIN out1[74]
    DIRECTION OUTPUT ;
    USE SIGNAL ;
    PORT
      LAYER M4 ;
        RECT 1926.8500 1639.4800 1926.9500 1640.0000 ;
    END
  END out1[74]
  PIN out1[73]
    DIRECTION OUTPUT ;
    USE SIGNAL ;
    PORT
      LAYER M4 ;
        RECT 1932.8500 1639.4800 1932.9500 1640.0000 ;
    END
  END out1[73]
  PIN out1[72]
    DIRECTION OUTPUT ;
    USE SIGNAL ;
    PORT
      LAYER M4 ;
        RECT 1938.8500 1639.4800 1938.9500 1640.0000 ;
    END
  END out1[72]
  PIN out1[71]
    DIRECTION OUTPUT ;
    USE SIGNAL ;
    PORT
      LAYER M4 ;
        RECT 1944.8500 1639.4800 1944.9500 1640.0000 ;
    END
  END out1[71]
  PIN out1[70]
    DIRECTION OUTPUT ;
    USE SIGNAL ;
    PORT
      LAYER M4 ;
        RECT 1950.8500 1639.4800 1950.9500 1640.0000 ;
    END
  END out1[70]
  PIN out1[69]
    DIRECTION OUTPUT ;
    USE SIGNAL ;
    PORT
      LAYER M4 ;
        RECT 1956.8500 1639.4800 1956.9500 1640.0000 ;
    END
  END out1[69]
  PIN out1[68]
    DIRECTION OUTPUT ;
    USE SIGNAL ;
    PORT
      LAYER M4 ;
        RECT 1962.8500 1639.4800 1962.9500 1640.0000 ;
    END
  END out1[68]
  PIN out1[67]
    DIRECTION OUTPUT ;
    USE SIGNAL ;
    PORT
      LAYER M4 ;
        RECT 1968.8500 1639.4800 1968.9500 1640.0000 ;
    END
  END out1[67]
  PIN out1[66]
    DIRECTION OUTPUT ;
    USE SIGNAL ;
    PORT
      LAYER M4 ;
        RECT 1974.8500 1639.4800 1974.9500 1640.0000 ;
    END
  END out1[66]
  PIN out1[65]
    DIRECTION OUTPUT ;
    USE SIGNAL ;
    PORT
      LAYER M4 ;
        RECT 1980.8500 1639.4800 1980.9500 1640.0000 ;
    END
  END out1[65]
  PIN out1[64]
    DIRECTION OUTPUT ;
    USE SIGNAL ;
    PORT
      LAYER M4 ;
        RECT 1986.8500 1639.4800 1986.9500 1640.0000 ;
    END
  END out1[64]
  PIN out1[63]
    DIRECTION OUTPUT ;
    USE SIGNAL ;
    PORT
      LAYER M4 ;
        RECT 1992.8500 1639.4800 1992.9500 1640.0000 ;
    END
  END out1[63]
  PIN out1[62]
    DIRECTION OUTPUT ;
    USE SIGNAL ;
    PORT
      LAYER M4 ;
        RECT 1998.8500 1639.4800 1998.9500 1640.0000 ;
    END
  END out1[62]
  PIN out1[61]
    DIRECTION OUTPUT ;
    USE SIGNAL ;
    PORT
      LAYER M4 ;
        RECT 2004.8500 1639.4800 2004.9500 1640.0000 ;
    END
  END out1[61]
  PIN out1[60]
    DIRECTION OUTPUT ;
    USE SIGNAL ;
    PORT
      LAYER M4 ;
        RECT 2010.8500 1639.4800 2010.9500 1640.0000 ;
    END
  END out1[60]
  PIN out1[59]
    DIRECTION OUTPUT ;
    USE SIGNAL ;
    PORT
      LAYER M4 ;
        RECT 2016.8500 1639.4800 2016.9500 1640.0000 ;
    END
  END out1[59]
  PIN out1[58]
    DIRECTION OUTPUT ;
    USE SIGNAL ;
    PORT
      LAYER M4 ;
        RECT 2022.8500 1639.4800 2022.9500 1640.0000 ;
    END
  END out1[58]
  PIN out1[57]
    DIRECTION OUTPUT ;
    USE SIGNAL ;
    PORT
      LAYER M4 ;
        RECT 2028.8500 1639.4800 2028.9500 1640.0000 ;
    END
  END out1[57]
  PIN out1[56]
    DIRECTION OUTPUT ;
    USE SIGNAL ;
    PORT
      LAYER M4 ;
        RECT 2034.8500 1639.4800 2034.9500 1640.0000 ;
    END
  END out1[56]
  PIN out1[55]
    DIRECTION OUTPUT ;
    USE SIGNAL ;
    PORT
      LAYER M4 ;
        RECT 2040.8500 1639.4800 2040.9500 1640.0000 ;
    END
  END out1[55]
  PIN out1[54]
    DIRECTION OUTPUT ;
    USE SIGNAL ;
    PORT
      LAYER M4 ;
        RECT 2046.8500 1639.4800 2046.9500 1640.0000 ;
    END
  END out1[54]
  PIN out1[53]
    DIRECTION OUTPUT ;
    USE SIGNAL ;
    PORT
      LAYER M4 ;
        RECT 2052.8500 1639.4800 2052.9500 1640.0000 ;
    END
  END out1[53]
  PIN out1[52]
    DIRECTION OUTPUT ;
    USE SIGNAL ;
    PORT
      LAYER M4 ;
        RECT 2058.8500 1639.4800 2058.9500 1640.0000 ;
    END
  END out1[52]
  PIN out1[51]
    DIRECTION OUTPUT ;
    USE SIGNAL ;
    PORT
      LAYER M4 ;
        RECT 2064.8500 1639.4800 2064.9500 1640.0000 ;
    END
  END out1[51]
  PIN out1[50]
    DIRECTION OUTPUT ;
    USE SIGNAL ;
    PORT
      LAYER M4 ;
        RECT 2070.8500 1639.4800 2070.9500 1640.0000 ;
    END
  END out1[50]
  PIN out1[49]
    DIRECTION OUTPUT ;
    USE SIGNAL ;
    PORT
      LAYER M4 ;
        RECT 2076.8500 1639.4800 2076.9500 1640.0000 ;
    END
  END out1[49]
  PIN out1[48]
    DIRECTION OUTPUT ;
    USE SIGNAL ;
    PORT
      LAYER M4 ;
        RECT 2082.8500 1639.4800 2082.9500 1640.0000 ;
    END
  END out1[48]
  PIN out1[47]
    DIRECTION OUTPUT ;
    USE SIGNAL ;
    PORT
      LAYER M4 ;
        RECT 2088.8500 1639.4800 2088.9500 1640.0000 ;
    END
  END out1[47]
  PIN out1[46]
    DIRECTION OUTPUT ;
    USE SIGNAL ;
    PORT
      LAYER M4 ;
        RECT 2094.8500 1639.4800 2094.9500 1640.0000 ;
    END
  END out1[46]
  PIN out1[45]
    DIRECTION OUTPUT ;
    USE SIGNAL ;
    PORT
      LAYER M4 ;
        RECT 2100.8500 1639.4800 2100.9500 1640.0000 ;
    END
  END out1[45]
  PIN out1[44]
    DIRECTION OUTPUT ;
    USE SIGNAL ;
    PORT
      LAYER M4 ;
        RECT 2106.8500 1639.4800 2106.9500 1640.0000 ;
    END
  END out1[44]
  PIN out1[43]
    DIRECTION OUTPUT ;
    USE SIGNAL ;
    PORT
      LAYER M4 ;
        RECT 2112.8500 1639.4800 2112.9500 1640.0000 ;
    END
  END out1[43]
  PIN out1[42]
    DIRECTION OUTPUT ;
    USE SIGNAL ;
    PORT
      LAYER M4 ;
        RECT 2118.8500 1639.4800 2118.9500 1640.0000 ;
    END
  END out1[42]
  PIN out1[41]
    DIRECTION OUTPUT ;
    USE SIGNAL ;
    PORT
      LAYER M4 ;
        RECT 2124.8500 1639.4800 2124.9500 1640.0000 ;
    END
  END out1[41]
  PIN out1[40]
    DIRECTION OUTPUT ;
    USE SIGNAL ;
    PORT
      LAYER M4 ;
        RECT 2130.8500 1639.4800 2130.9500 1640.0000 ;
    END
  END out1[40]
  PIN out1[39]
    DIRECTION OUTPUT ;
    USE SIGNAL ;
    PORT
      LAYER M4 ;
        RECT 2136.8500 1639.4800 2136.9500 1640.0000 ;
    END
  END out1[39]
  PIN out1[38]
    DIRECTION OUTPUT ;
    USE SIGNAL ;
    PORT
      LAYER M4 ;
        RECT 2142.8500 1639.4800 2142.9500 1640.0000 ;
    END
  END out1[38]
  PIN out1[37]
    DIRECTION OUTPUT ;
    USE SIGNAL ;
    PORT
      LAYER M4 ;
        RECT 2148.8500 1639.4800 2148.9500 1640.0000 ;
    END
  END out1[37]
  PIN out1[36]
    DIRECTION OUTPUT ;
    USE SIGNAL ;
    PORT
      LAYER M4 ;
        RECT 2154.8500 1639.4800 2154.9500 1640.0000 ;
    END
  END out1[36]
  PIN out1[35]
    DIRECTION OUTPUT ;
    USE SIGNAL ;
    PORT
      LAYER M4 ;
        RECT 2160.8500 1639.4800 2160.9500 1640.0000 ;
    END
  END out1[35]
  PIN out1[34]
    DIRECTION OUTPUT ;
    USE SIGNAL ;
    PORT
      LAYER M4 ;
        RECT 2166.8500 1639.4800 2166.9500 1640.0000 ;
    END
  END out1[34]
  PIN out1[33]
    DIRECTION OUTPUT ;
    USE SIGNAL ;
    PORT
      LAYER M4 ;
        RECT 2172.8500 1639.4800 2172.9500 1640.0000 ;
    END
  END out1[33]
  PIN out1[32]
    DIRECTION OUTPUT ;
    USE SIGNAL ;
    PORT
      LAYER M4 ;
        RECT 2178.8500 1639.4800 2178.9500 1640.0000 ;
    END
  END out1[32]
  PIN out1[31]
    DIRECTION OUTPUT ;
    USE SIGNAL ;
    PORT
      LAYER M4 ;
        RECT 2184.8500 1639.4800 2184.9500 1640.0000 ;
    END
  END out1[31]
  PIN out1[30]
    DIRECTION OUTPUT ;
    USE SIGNAL ;
    PORT
      LAYER M4 ;
        RECT 2190.8500 1639.4800 2190.9500 1640.0000 ;
    END
  END out1[30]
  PIN out1[29]
    DIRECTION OUTPUT ;
    USE SIGNAL ;
    PORT
      LAYER M4 ;
        RECT 2196.8500 1639.4800 2196.9500 1640.0000 ;
    END
  END out1[29]
  PIN out1[28]
    DIRECTION OUTPUT ;
    USE SIGNAL ;
    PORT
      LAYER M4 ;
        RECT 2202.8500 1639.4800 2202.9500 1640.0000 ;
    END
  END out1[28]
  PIN out1[27]
    DIRECTION OUTPUT ;
    USE SIGNAL ;
    PORT
      LAYER M4 ;
        RECT 2208.8500 1639.4800 2208.9500 1640.0000 ;
    END
  END out1[27]
  PIN out1[26]
    DIRECTION OUTPUT ;
    USE SIGNAL ;
    PORT
      LAYER M4 ;
        RECT 2214.8500 1639.4800 2214.9500 1640.0000 ;
    END
  END out1[26]
  PIN out1[25]
    DIRECTION OUTPUT ;
    USE SIGNAL ;
    PORT
      LAYER M4 ;
        RECT 2220.8500 1639.4800 2220.9500 1640.0000 ;
    END
  END out1[25]
  PIN out1[24]
    DIRECTION OUTPUT ;
    USE SIGNAL ;
    PORT
      LAYER M4 ;
        RECT 2226.8500 1639.4800 2226.9500 1640.0000 ;
    END
  END out1[24]
  PIN out1[23]
    DIRECTION OUTPUT ;
    USE SIGNAL ;
    PORT
      LAYER M4 ;
        RECT 2232.8500 1639.4800 2232.9500 1640.0000 ;
    END
  END out1[23]
  PIN out1[22]
    DIRECTION OUTPUT ;
    USE SIGNAL ;
    PORT
      LAYER M4 ;
        RECT 2238.8500 1639.4800 2238.9500 1640.0000 ;
    END
  END out1[22]
  PIN out1[21]
    DIRECTION OUTPUT ;
    USE SIGNAL ;
    PORT
      LAYER M4 ;
        RECT 2244.8500 1639.4800 2244.9500 1640.0000 ;
    END
  END out1[21]
  PIN out1[20]
    DIRECTION OUTPUT ;
    USE SIGNAL ;
    PORT
      LAYER M4 ;
        RECT 2250.8500 1639.4800 2250.9500 1640.0000 ;
    END
  END out1[20]
  PIN out1[19]
    DIRECTION OUTPUT ;
    USE SIGNAL ;
    PORT
      LAYER M4 ;
        RECT 2256.8500 1639.4800 2256.9500 1640.0000 ;
    END
  END out1[19]
  PIN out1[18]
    DIRECTION OUTPUT ;
    USE SIGNAL ;
    PORT
      LAYER M4 ;
        RECT 2262.8500 1639.4800 2262.9500 1640.0000 ;
    END
  END out1[18]
  PIN out1[17]
    DIRECTION OUTPUT ;
    USE SIGNAL ;
    PORT
      LAYER M4 ;
        RECT 2268.8500 1639.4800 2268.9500 1640.0000 ;
    END
  END out1[17]
  PIN out1[16]
    DIRECTION OUTPUT ;
    USE SIGNAL ;
    PORT
      LAYER M4 ;
        RECT 2274.8500 1639.4800 2274.9500 1640.0000 ;
    END
  END out1[16]
  PIN out1[15]
    DIRECTION OUTPUT ;
    USE SIGNAL ;
    PORT
      LAYER M4 ;
        RECT 2280.8500 1639.4800 2280.9500 1640.0000 ;
    END
  END out1[15]
  PIN out1[14]
    DIRECTION OUTPUT ;
    USE SIGNAL ;
    PORT
      LAYER M4 ;
        RECT 2286.8500 1639.4800 2286.9500 1640.0000 ;
    END
  END out1[14]
  PIN out1[13]
    DIRECTION OUTPUT ;
    USE SIGNAL ;
    PORT
      LAYER M4 ;
        RECT 2292.8500 1639.4800 2292.9500 1640.0000 ;
    END
  END out1[13]
  PIN out1[12]
    DIRECTION OUTPUT ;
    USE SIGNAL ;
    PORT
      LAYER M4 ;
        RECT 2298.8500 1639.4800 2298.9500 1640.0000 ;
    END
  END out1[12]
  PIN out1[11]
    DIRECTION OUTPUT ;
    USE SIGNAL ;
    PORT
      LAYER M4 ;
        RECT 2304.8500 1639.4800 2304.9500 1640.0000 ;
    END
  END out1[11]
  PIN out1[10]
    DIRECTION OUTPUT ;
    USE SIGNAL ;
    PORT
      LAYER M4 ;
        RECT 2310.8500 1639.4800 2310.9500 1640.0000 ;
    END
  END out1[10]
  PIN out1[9]
    DIRECTION OUTPUT ;
    USE SIGNAL ;
    PORT
      LAYER M4 ;
        RECT 2316.8500 1639.4800 2316.9500 1640.0000 ;
    END
  END out1[9]
  PIN out1[8]
    DIRECTION OUTPUT ;
    USE SIGNAL ;
    PORT
      LAYER M4 ;
        RECT 2322.8500 1639.4800 2322.9500 1640.0000 ;
    END
  END out1[8]
  PIN out1[7]
    DIRECTION OUTPUT ;
    USE SIGNAL ;
    PORT
      LAYER M4 ;
        RECT 2328.8500 1639.4800 2328.9500 1640.0000 ;
    END
  END out1[7]
  PIN out1[6]
    DIRECTION OUTPUT ;
    USE SIGNAL ;
    PORT
      LAYER M4 ;
        RECT 2334.8500 1639.4800 2334.9500 1640.0000 ;
    END
  END out1[6]
  PIN out1[5]
    DIRECTION OUTPUT ;
    USE SIGNAL ;
    PORT
      LAYER M4 ;
        RECT 2340.8500 1639.4800 2340.9500 1640.0000 ;
    END
  END out1[5]
  PIN out1[4]
    DIRECTION OUTPUT ;
    USE SIGNAL ;
    PORT
      LAYER M4 ;
        RECT 2346.8500 1639.4800 2346.9500 1640.0000 ;
    END
  END out1[4]
  PIN out1[3]
    DIRECTION OUTPUT ;
    USE SIGNAL ;
    PORT
      LAYER M4 ;
        RECT 2352.8500 1639.4800 2352.9500 1640.0000 ;
    END
  END out1[3]
  PIN out1[2]
    DIRECTION OUTPUT ;
    USE SIGNAL ;
    PORT
      LAYER M4 ;
        RECT 2358.8500 1639.4800 2358.9500 1640.0000 ;
    END
  END out1[2]
  PIN out1[1]
    DIRECTION OUTPUT ;
    USE SIGNAL ;
    PORT
      LAYER M4 ;
        RECT 2364.8500 1639.4800 2364.9500 1640.0000 ;
    END
  END out1[1]
  PIN out1[0]
    DIRECTION OUTPUT ;
    USE SIGNAL ;
    PORT
      LAYER M4 ;
        RECT 2370.8500 1639.4800 2370.9500 1640.0000 ;
    END
  END out1[0]
  PIN fifo0_empty
    DIRECTION OUTPUT ;
    USE SIGNAL ;
    PORT
      LAYER M4 ;
        RECT 2376.8500 1639.4800 2376.9500 1640.0000 ;
    END
  END fifo0_empty
  PIN fifo1_empty
    DIRECTION OUTPUT ;
    USE SIGNAL ;
    PORT
      LAYER M4 ;
        RECT 2382.8500 1639.4800 2382.9500 1640.0000 ;
    END
  END fifo1_empty
  OBS
    LAYER M1 ;
      RECT 0.0000 0.0000 2840.0000 1640.0000 ;
    LAYER M2 ;
      RECT 0.0000 0.0000 2840.0000 1640.0000 ;
    LAYER M3 ;
      RECT 0.0000 823.3500 2840.0000 1640.0000 ;
      RECT 0.0000 823.0500 2839.3800 823.3500 ;
      RECT 0.0000 822.9500 2840.0000 823.0500 ;
      RECT 0.6200 822.6500 2840.0000 822.9500 ;
      RECT 0.0000 817.3500 2840.0000 822.6500 ;
      RECT 0.0000 817.0500 2839.3800 817.3500 ;
      RECT 0.0000 816.9500 2840.0000 817.0500 ;
      RECT 0.6200 816.6500 2840.0000 816.9500 ;
      RECT 0.0000 0.0000 2840.0000 816.6500 ;
    LAYER M4 ;
      RECT 2383.0500 1639.3800 2840.0000 1640.0000 ;
      RECT 2377.0500 1639.3800 2382.7500 1640.0000 ;
      RECT 2371.0500 1639.3800 2376.7500 1640.0000 ;
      RECT 2365.0500 1639.3800 2370.7500 1640.0000 ;
      RECT 2359.0500 1639.3800 2364.7500 1640.0000 ;
      RECT 2353.0500 1639.3800 2358.7500 1640.0000 ;
      RECT 2347.0500 1639.3800 2352.7500 1640.0000 ;
      RECT 2341.0500 1639.3800 2346.7500 1640.0000 ;
      RECT 2335.0500 1639.3800 2340.7500 1640.0000 ;
      RECT 2329.0500 1639.3800 2334.7500 1640.0000 ;
      RECT 2323.0500 1639.3800 2328.7500 1640.0000 ;
      RECT 2317.0500 1639.3800 2322.7500 1640.0000 ;
      RECT 2311.0500 1639.3800 2316.7500 1640.0000 ;
      RECT 2305.0500 1639.3800 2310.7500 1640.0000 ;
      RECT 2299.0500 1639.3800 2304.7500 1640.0000 ;
      RECT 2293.0500 1639.3800 2298.7500 1640.0000 ;
      RECT 2287.0500 1639.3800 2292.7500 1640.0000 ;
      RECT 2281.0500 1639.3800 2286.7500 1640.0000 ;
      RECT 2275.0500 1639.3800 2280.7500 1640.0000 ;
      RECT 2269.0500 1639.3800 2274.7500 1640.0000 ;
      RECT 2263.0500 1639.3800 2268.7500 1640.0000 ;
      RECT 2257.0500 1639.3800 2262.7500 1640.0000 ;
      RECT 2251.0500 1639.3800 2256.7500 1640.0000 ;
      RECT 2245.0500 1639.3800 2250.7500 1640.0000 ;
      RECT 2239.0500 1639.3800 2244.7500 1640.0000 ;
      RECT 2233.0500 1639.3800 2238.7500 1640.0000 ;
      RECT 2227.0500 1639.3800 2232.7500 1640.0000 ;
      RECT 2221.0500 1639.3800 2226.7500 1640.0000 ;
      RECT 2215.0500 1639.3800 2220.7500 1640.0000 ;
      RECT 2209.0500 1639.3800 2214.7500 1640.0000 ;
      RECT 2203.0500 1639.3800 2208.7500 1640.0000 ;
      RECT 2197.0500 1639.3800 2202.7500 1640.0000 ;
      RECT 2191.0500 1639.3800 2196.7500 1640.0000 ;
      RECT 2185.0500 1639.3800 2190.7500 1640.0000 ;
      RECT 2179.0500 1639.3800 2184.7500 1640.0000 ;
      RECT 2173.0500 1639.3800 2178.7500 1640.0000 ;
      RECT 2167.0500 1639.3800 2172.7500 1640.0000 ;
      RECT 2161.0500 1639.3800 2166.7500 1640.0000 ;
      RECT 2155.0500 1639.3800 2160.7500 1640.0000 ;
      RECT 2149.0500 1639.3800 2154.7500 1640.0000 ;
      RECT 2143.0500 1639.3800 2148.7500 1640.0000 ;
      RECT 2137.0500 1639.3800 2142.7500 1640.0000 ;
      RECT 2131.0500 1639.3800 2136.7500 1640.0000 ;
      RECT 2125.0500 1639.3800 2130.7500 1640.0000 ;
      RECT 2119.0500 1639.3800 2124.7500 1640.0000 ;
      RECT 2113.0500 1639.3800 2118.7500 1640.0000 ;
      RECT 2107.0500 1639.3800 2112.7500 1640.0000 ;
      RECT 2101.0500 1639.3800 2106.7500 1640.0000 ;
      RECT 2095.0500 1639.3800 2100.7500 1640.0000 ;
      RECT 2089.0500 1639.3800 2094.7500 1640.0000 ;
      RECT 2083.0500 1639.3800 2088.7500 1640.0000 ;
      RECT 2077.0500 1639.3800 2082.7500 1640.0000 ;
      RECT 2071.0500 1639.3800 2076.7500 1640.0000 ;
      RECT 2065.0500 1639.3800 2070.7500 1640.0000 ;
      RECT 2059.0500 1639.3800 2064.7500 1640.0000 ;
      RECT 2053.0500 1639.3800 2058.7500 1640.0000 ;
      RECT 2047.0500 1639.3800 2052.7500 1640.0000 ;
      RECT 2041.0500 1639.3800 2046.7500 1640.0000 ;
      RECT 2035.0500 1639.3800 2040.7500 1640.0000 ;
      RECT 2029.0500 1639.3800 2034.7500 1640.0000 ;
      RECT 2023.0500 1639.3800 2028.7500 1640.0000 ;
      RECT 2017.0500 1639.3800 2022.7500 1640.0000 ;
      RECT 2011.0500 1639.3800 2016.7500 1640.0000 ;
      RECT 2005.0500 1639.3800 2010.7500 1640.0000 ;
      RECT 1999.0500 1639.3800 2004.7500 1640.0000 ;
      RECT 1993.0500 1639.3800 1998.7500 1640.0000 ;
      RECT 1987.0500 1639.3800 1992.7500 1640.0000 ;
      RECT 1981.0500 1639.3800 1986.7500 1640.0000 ;
      RECT 1975.0500 1639.3800 1980.7500 1640.0000 ;
      RECT 1969.0500 1639.3800 1974.7500 1640.0000 ;
      RECT 1963.0500 1639.3800 1968.7500 1640.0000 ;
      RECT 1957.0500 1639.3800 1962.7500 1640.0000 ;
      RECT 1951.0500 1639.3800 1956.7500 1640.0000 ;
      RECT 1945.0500 1639.3800 1950.7500 1640.0000 ;
      RECT 1939.0500 1639.3800 1944.7500 1640.0000 ;
      RECT 1933.0500 1639.3800 1938.7500 1640.0000 ;
      RECT 1927.0500 1639.3800 1932.7500 1640.0000 ;
      RECT 1921.0500 1639.3800 1926.7500 1640.0000 ;
      RECT 1915.0500 1639.3800 1920.7500 1640.0000 ;
      RECT 1909.0500 1639.3800 1914.7500 1640.0000 ;
      RECT 1903.0500 1639.3800 1908.7500 1640.0000 ;
      RECT 1897.0500 1639.3800 1902.7500 1640.0000 ;
      RECT 1891.0500 1639.3800 1896.7500 1640.0000 ;
      RECT 1885.0500 1639.3800 1890.7500 1640.0000 ;
      RECT 1879.0500 1639.3800 1884.7500 1640.0000 ;
      RECT 1873.0500 1639.3800 1878.7500 1640.0000 ;
      RECT 1867.0500 1639.3800 1872.7500 1640.0000 ;
      RECT 1861.0500 1639.3800 1866.7500 1640.0000 ;
      RECT 1855.0500 1639.3800 1860.7500 1640.0000 ;
      RECT 1849.0500 1639.3800 1854.7500 1640.0000 ;
      RECT 1843.0500 1639.3800 1848.7500 1640.0000 ;
      RECT 1837.0500 1639.3800 1842.7500 1640.0000 ;
      RECT 1831.0500 1639.3800 1836.7500 1640.0000 ;
      RECT 1825.0500 1639.3800 1830.7500 1640.0000 ;
      RECT 1819.0500 1639.3800 1824.7500 1640.0000 ;
      RECT 1813.0500 1639.3800 1818.7500 1640.0000 ;
      RECT 1807.0500 1639.3800 1812.7500 1640.0000 ;
      RECT 1801.0500 1639.3800 1806.7500 1640.0000 ;
      RECT 1795.0500 1639.3800 1800.7500 1640.0000 ;
      RECT 1789.0500 1639.3800 1794.7500 1640.0000 ;
      RECT 1783.0500 1639.3800 1788.7500 1640.0000 ;
      RECT 1777.0500 1639.3800 1782.7500 1640.0000 ;
      RECT 1771.0500 1639.3800 1776.7500 1640.0000 ;
      RECT 1765.0500 1639.3800 1770.7500 1640.0000 ;
      RECT 1759.0500 1639.3800 1764.7500 1640.0000 ;
      RECT 1753.0500 1639.3800 1758.7500 1640.0000 ;
      RECT 1747.0500 1639.3800 1752.7500 1640.0000 ;
      RECT 1741.0500 1639.3800 1746.7500 1640.0000 ;
      RECT 1735.0500 1639.3800 1740.7500 1640.0000 ;
      RECT 1729.0500 1639.3800 1734.7500 1640.0000 ;
      RECT 1723.0500 1639.3800 1728.7500 1640.0000 ;
      RECT 1717.0500 1639.3800 1722.7500 1640.0000 ;
      RECT 1711.0500 1639.3800 1716.7500 1640.0000 ;
      RECT 1705.0500 1639.3800 1710.7500 1640.0000 ;
      RECT 1699.0500 1639.3800 1704.7500 1640.0000 ;
      RECT 1693.0500 1639.3800 1698.7500 1640.0000 ;
      RECT 1687.0500 1639.3800 1692.7500 1640.0000 ;
      RECT 1681.0500 1639.3800 1686.7500 1640.0000 ;
      RECT 1675.0500 1639.3800 1680.7500 1640.0000 ;
      RECT 1669.0500 1639.3800 1674.7500 1640.0000 ;
      RECT 1663.0500 1639.3800 1668.7500 1640.0000 ;
      RECT 1657.0500 1639.3800 1662.7500 1640.0000 ;
      RECT 1651.0500 1639.3800 1656.7500 1640.0000 ;
      RECT 1645.0500 1639.3800 1650.7500 1640.0000 ;
      RECT 1639.0500 1639.3800 1644.7500 1640.0000 ;
      RECT 1633.0500 1639.3800 1638.7500 1640.0000 ;
      RECT 1627.0500 1639.3800 1632.7500 1640.0000 ;
      RECT 1621.0500 1639.3800 1626.7500 1640.0000 ;
      RECT 1615.0500 1639.3800 1620.7500 1640.0000 ;
      RECT 1609.0500 1639.3800 1614.7500 1640.0000 ;
      RECT 1603.0500 1639.3800 1608.7500 1640.0000 ;
      RECT 1597.0500 1639.3800 1602.7500 1640.0000 ;
      RECT 1591.0500 1639.3800 1596.7500 1640.0000 ;
      RECT 1585.0500 1639.3800 1590.7500 1640.0000 ;
      RECT 1579.0500 1639.3800 1584.7500 1640.0000 ;
      RECT 1573.0500 1639.3800 1578.7500 1640.0000 ;
      RECT 1567.0500 1639.3800 1572.7500 1640.0000 ;
      RECT 1561.0500 1639.3800 1566.7500 1640.0000 ;
      RECT 1555.0500 1639.3800 1560.7500 1640.0000 ;
      RECT 1549.0500 1639.3800 1554.7500 1640.0000 ;
      RECT 1543.0500 1639.3800 1548.7500 1640.0000 ;
      RECT 1537.0500 1639.3800 1542.7500 1640.0000 ;
      RECT 1531.0500 1639.3800 1536.7500 1640.0000 ;
      RECT 1525.0500 1639.3800 1530.7500 1640.0000 ;
      RECT 1519.0500 1639.3800 1524.7500 1640.0000 ;
      RECT 1513.0500 1639.3800 1518.7500 1640.0000 ;
      RECT 1507.0500 1639.3800 1512.7500 1640.0000 ;
      RECT 1501.0500 1639.3800 1506.7500 1640.0000 ;
      RECT 1495.0500 1639.3800 1500.7500 1640.0000 ;
      RECT 1489.0500 1639.3800 1494.7500 1640.0000 ;
      RECT 1483.0500 1639.3800 1488.7500 1640.0000 ;
      RECT 1477.0500 1639.3800 1482.7500 1640.0000 ;
      RECT 1471.0500 1639.3800 1476.7500 1640.0000 ;
      RECT 1465.0500 1639.3800 1470.7500 1640.0000 ;
      RECT 1459.0500 1639.3800 1464.7500 1640.0000 ;
      RECT 1453.0500 1639.3800 1458.7500 1640.0000 ;
      RECT 1447.0500 1639.3800 1452.7500 1640.0000 ;
      RECT 1441.0500 1639.3800 1446.7500 1640.0000 ;
      RECT 1435.0500 1639.3800 1440.7500 1640.0000 ;
      RECT 1429.0500 1639.3800 1434.7500 1640.0000 ;
      RECT 1423.0500 1639.3800 1428.7500 1640.0000 ;
      RECT 1417.0500 1639.3800 1422.7500 1640.0000 ;
      RECT 1411.0500 1639.3800 1416.7500 1640.0000 ;
      RECT 1405.0500 1639.3800 1410.7500 1640.0000 ;
      RECT 1399.0500 1639.3800 1404.7500 1640.0000 ;
      RECT 1393.0500 1639.3800 1398.7500 1640.0000 ;
      RECT 1387.0500 1639.3800 1392.7500 1640.0000 ;
      RECT 1381.0500 1639.3800 1386.7500 1640.0000 ;
      RECT 1375.0500 1639.3800 1380.7500 1640.0000 ;
      RECT 1369.0500 1639.3800 1374.7500 1640.0000 ;
      RECT 1363.0500 1639.3800 1368.7500 1640.0000 ;
      RECT 1357.0500 1639.3800 1362.7500 1640.0000 ;
      RECT 1351.0500 1639.3800 1356.7500 1640.0000 ;
      RECT 1345.0500 1639.3800 1350.7500 1640.0000 ;
      RECT 1339.0500 1639.3800 1344.7500 1640.0000 ;
      RECT 1333.0500 1639.3800 1338.7500 1640.0000 ;
      RECT 1327.0500 1639.3800 1332.7500 1640.0000 ;
      RECT 1321.0500 1639.3800 1326.7500 1640.0000 ;
      RECT 1315.0500 1639.3800 1320.7500 1640.0000 ;
      RECT 1309.0500 1639.3800 1314.7500 1640.0000 ;
      RECT 1303.0500 1639.3800 1308.7500 1640.0000 ;
      RECT 1297.0500 1639.3800 1302.7500 1640.0000 ;
      RECT 1291.0500 1639.3800 1296.7500 1640.0000 ;
      RECT 1285.0500 1639.3800 1290.7500 1640.0000 ;
      RECT 1279.0500 1639.3800 1284.7500 1640.0000 ;
      RECT 1273.0500 1639.3800 1278.7500 1640.0000 ;
      RECT 1267.0500 1639.3800 1272.7500 1640.0000 ;
      RECT 1261.0500 1639.3800 1266.7500 1640.0000 ;
      RECT 1255.0500 1639.3800 1260.7500 1640.0000 ;
      RECT 1249.0500 1639.3800 1254.7500 1640.0000 ;
      RECT 1243.0500 1639.3800 1248.7500 1640.0000 ;
      RECT 1237.0500 1639.3800 1242.7500 1640.0000 ;
      RECT 1231.0500 1639.3800 1236.7500 1640.0000 ;
      RECT 1225.0500 1639.3800 1230.7500 1640.0000 ;
      RECT 1219.0500 1639.3800 1224.7500 1640.0000 ;
      RECT 1213.0500 1639.3800 1218.7500 1640.0000 ;
      RECT 1207.0500 1639.3800 1212.7500 1640.0000 ;
      RECT 1201.0500 1639.3800 1206.7500 1640.0000 ;
      RECT 1195.0500 1639.3800 1200.7500 1640.0000 ;
      RECT 1189.0500 1639.3800 1194.7500 1640.0000 ;
      RECT 1183.0500 1639.3800 1188.7500 1640.0000 ;
      RECT 1177.0500 1639.3800 1182.7500 1640.0000 ;
      RECT 1171.0500 1639.3800 1176.7500 1640.0000 ;
      RECT 1165.0500 1639.3800 1170.7500 1640.0000 ;
      RECT 1159.0500 1639.3800 1164.7500 1640.0000 ;
      RECT 1153.0500 1639.3800 1158.7500 1640.0000 ;
      RECT 1147.0500 1639.3800 1152.7500 1640.0000 ;
      RECT 1141.0500 1639.3800 1146.7500 1640.0000 ;
      RECT 1135.0500 1639.3800 1140.7500 1640.0000 ;
      RECT 1129.0500 1639.3800 1134.7500 1640.0000 ;
      RECT 1123.0500 1639.3800 1128.7500 1640.0000 ;
      RECT 1117.0500 1639.3800 1122.7500 1640.0000 ;
      RECT 1111.0500 1639.3800 1116.7500 1640.0000 ;
      RECT 1105.0500 1639.3800 1110.7500 1640.0000 ;
      RECT 1099.0500 1639.3800 1104.7500 1640.0000 ;
      RECT 1093.0500 1639.3800 1098.7500 1640.0000 ;
      RECT 1087.0500 1639.3800 1092.7500 1640.0000 ;
      RECT 1081.0500 1639.3800 1086.7500 1640.0000 ;
      RECT 1075.0500 1639.3800 1080.7500 1640.0000 ;
      RECT 1069.0500 1639.3800 1074.7500 1640.0000 ;
      RECT 1063.0500 1639.3800 1068.7500 1640.0000 ;
      RECT 1057.0500 1639.3800 1062.7500 1640.0000 ;
      RECT 1051.0500 1639.3800 1056.7500 1640.0000 ;
      RECT 1045.0500 1639.3800 1050.7500 1640.0000 ;
      RECT 1039.0500 1639.3800 1044.7500 1640.0000 ;
      RECT 1033.0500 1639.3800 1038.7500 1640.0000 ;
      RECT 1027.0500 1639.3800 1032.7500 1640.0000 ;
      RECT 1021.0500 1639.3800 1026.7500 1640.0000 ;
      RECT 1015.0500 1639.3800 1020.7500 1640.0000 ;
      RECT 1009.0500 1639.3800 1014.7500 1640.0000 ;
      RECT 1003.0500 1639.3800 1008.7500 1640.0000 ;
      RECT 997.0500 1639.3800 1002.7500 1640.0000 ;
      RECT 991.0500 1639.3800 996.7500 1640.0000 ;
      RECT 985.0500 1639.3800 990.7500 1640.0000 ;
      RECT 979.0500 1639.3800 984.7500 1640.0000 ;
      RECT 973.0500 1639.3800 978.7500 1640.0000 ;
      RECT 967.0500 1639.3800 972.7500 1640.0000 ;
      RECT 961.0500 1639.3800 966.7500 1640.0000 ;
      RECT 955.0500 1639.3800 960.7500 1640.0000 ;
      RECT 949.0500 1639.3800 954.7500 1640.0000 ;
      RECT 943.0500 1639.3800 948.7500 1640.0000 ;
      RECT 937.0500 1639.3800 942.7500 1640.0000 ;
      RECT 931.0500 1639.3800 936.7500 1640.0000 ;
      RECT 925.0500 1639.3800 930.7500 1640.0000 ;
      RECT 919.0500 1639.3800 924.7500 1640.0000 ;
      RECT 913.0500 1639.3800 918.7500 1640.0000 ;
      RECT 907.0500 1639.3800 912.7500 1640.0000 ;
      RECT 901.0500 1639.3800 906.7500 1640.0000 ;
      RECT 895.0500 1639.3800 900.7500 1640.0000 ;
      RECT 889.0500 1639.3800 894.7500 1640.0000 ;
      RECT 883.0500 1639.3800 888.7500 1640.0000 ;
      RECT 877.0500 1639.3800 882.7500 1640.0000 ;
      RECT 871.0500 1639.3800 876.7500 1640.0000 ;
      RECT 865.0500 1639.3800 870.7500 1640.0000 ;
      RECT 859.0500 1639.3800 864.7500 1640.0000 ;
      RECT 853.0500 1639.3800 858.7500 1640.0000 ;
      RECT 847.0500 1639.3800 852.7500 1640.0000 ;
      RECT 841.0500 1639.3800 846.7500 1640.0000 ;
      RECT 835.0500 1639.3800 840.7500 1640.0000 ;
      RECT 829.0500 1639.3800 834.7500 1640.0000 ;
      RECT 823.0500 1639.3800 828.7500 1640.0000 ;
      RECT 817.0500 1639.3800 822.7500 1640.0000 ;
      RECT 811.0500 1639.3800 816.7500 1640.0000 ;
      RECT 805.0500 1639.3800 810.7500 1640.0000 ;
      RECT 799.0500 1639.3800 804.7500 1640.0000 ;
      RECT 793.0500 1639.3800 798.7500 1640.0000 ;
      RECT 787.0500 1639.3800 792.7500 1640.0000 ;
      RECT 781.0500 1639.3800 786.7500 1640.0000 ;
      RECT 775.0500 1639.3800 780.7500 1640.0000 ;
      RECT 769.0500 1639.3800 774.7500 1640.0000 ;
      RECT 763.0500 1639.3800 768.7500 1640.0000 ;
      RECT 757.0500 1639.3800 762.7500 1640.0000 ;
      RECT 751.0500 1639.3800 756.7500 1640.0000 ;
      RECT 745.0500 1639.3800 750.7500 1640.0000 ;
      RECT 739.0500 1639.3800 744.7500 1640.0000 ;
      RECT 733.0500 1639.3800 738.7500 1640.0000 ;
      RECT 727.0500 1639.3800 732.7500 1640.0000 ;
      RECT 721.0500 1639.3800 726.7500 1640.0000 ;
      RECT 715.0500 1639.3800 720.7500 1640.0000 ;
      RECT 709.0500 1639.3800 714.7500 1640.0000 ;
      RECT 703.0500 1639.3800 708.7500 1640.0000 ;
      RECT 697.0500 1639.3800 702.7500 1640.0000 ;
      RECT 691.0500 1639.3800 696.7500 1640.0000 ;
      RECT 685.0500 1639.3800 690.7500 1640.0000 ;
      RECT 679.0500 1639.3800 684.7500 1640.0000 ;
      RECT 673.0500 1639.3800 678.7500 1640.0000 ;
      RECT 667.0500 1639.3800 672.7500 1640.0000 ;
      RECT 661.0500 1639.3800 666.7500 1640.0000 ;
      RECT 655.0500 1639.3800 660.7500 1640.0000 ;
      RECT 649.0500 1639.3800 654.7500 1640.0000 ;
      RECT 643.0500 1639.3800 648.7500 1640.0000 ;
      RECT 637.0500 1639.3800 642.7500 1640.0000 ;
      RECT 631.0500 1639.3800 636.7500 1640.0000 ;
      RECT 625.0500 1639.3800 630.7500 1640.0000 ;
      RECT 619.0500 1639.3800 624.7500 1640.0000 ;
      RECT 613.0500 1639.3800 618.7500 1640.0000 ;
      RECT 607.0500 1639.3800 612.7500 1640.0000 ;
      RECT 601.0500 1639.3800 606.7500 1640.0000 ;
      RECT 595.0500 1639.3800 600.7500 1640.0000 ;
      RECT 589.0500 1639.3800 594.7500 1640.0000 ;
      RECT 583.0500 1639.3800 588.7500 1640.0000 ;
      RECT 577.0500 1639.3800 582.7500 1640.0000 ;
      RECT 571.0500 1639.3800 576.7500 1640.0000 ;
      RECT 565.0500 1639.3800 570.7500 1640.0000 ;
      RECT 559.0500 1639.3800 564.7500 1640.0000 ;
      RECT 553.0500 1639.3800 558.7500 1640.0000 ;
      RECT 547.0500 1639.3800 552.7500 1640.0000 ;
      RECT 541.0500 1639.3800 546.7500 1640.0000 ;
      RECT 535.0500 1639.3800 540.7500 1640.0000 ;
      RECT 529.0500 1639.3800 534.7500 1640.0000 ;
      RECT 523.0500 1639.3800 528.7500 1640.0000 ;
      RECT 517.0500 1639.3800 522.7500 1640.0000 ;
      RECT 511.0500 1639.3800 516.7500 1640.0000 ;
      RECT 505.0500 1639.3800 510.7500 1640.0000 ;
      RECT 499.0500 1639.3800 504.7500 1640.0000 ;
      RECT 493.0500 1639.3800 498.7500 1640.0000 ;
      RECT 487.0500 1639.3800 492.7500 1640.0000 ;
      RECT 481.0500 1639.3800 486.7500 1640.0000 ;
      RECT 475.0500 1639.3800 480.7500 1640.0000 ;
      RECT 469.0500 1639.3800 474.7500 1640.0000 ;
      RECT 463.0500 1639.3800 468.7500 1640.0000 ;
      RECT 457.0500 1639.3800 462.7500 1640.0000 ;
      RECT 0.0000 1639.3800 456.7500 1640.0000 ;
      RECT 0.0000 0.6200 2840.0000 1639.3800 ;
      RECT 2088.2500 0.0000 2840.0000 0.6200 ;
      RECT 2080.2500 0.0000 2087.9500 0.6200 ;
      RECT 2072.2500 0.0000 2079.9500 0.6200 ;
      RECT 2064.2500 0.0000 2071.9500 0.6200 ;
      RECT 2056.2500 0.0000 2063.9500 0.6200 ;
      RECT 2048.2500 0.0000 2055.9500 0.6200 ;
      RECT 2040.2500 0.0000 2047.9500 0.6200 ;
      RECT 2032.2500 0.0000 2039.9500 0.6200 ;
      RECT 2024.2500 0.0000 2031.9500 0.6200 ;
      RECT 2016.2500 0.0000 2023.9500 0.6200 ;
      RECT 2008.2500 0.0000 2015.9500 0.6200 ;
      RECT 2000.2500 0.0000 2007.9500 0.6200 ;
      RECT 1992.2500 0.0000 1999.9500 0.6200 ;
      RECT 1984.2500 0.0000 1991.9500 0.6200 ;
      RECT 1976.2500 0.0000 1983.9500 0.6200 ;
      RECT 1968.2500 0.0000 1975.9500 0.6200 ;
      RECT 1960.2500 0.0000 1967.9500 0.6200 ;
      RECT 1952.2500 0.0000 1959.9500 0.6200 ;
      RECT 1944.2500 0.0000 1951.9500 0.6200 ;
      RECT 1936.2500 0.0000 1943.9500 0.6200 ;
      RECT 1928.2500 0.0000 1935.9500 0.6200 ;
      RECT 1920.2500 0.0000 1927.9500 0.6200 ;
      RECT 1912.2500 0.0000 1919.9500 0.6200 ;
      RECT 1904.2500 0.0000 1911.9500 0.6200 ;
      RECT 1896.2500 0.0000 1903.9500 0.6200 ;
      RECT 1888.2500 0.0000 1895.9500 0.6200 ;
      RECT 1880.2500 0.0000 1887.9500 0.6200 ;
      RECT 1872.2500 0.0000 1879.9500 0.6200 ;
      RECT 1864.2500 0.0000 1871.9500 0.6200 ;
      RECT 1856.2500 0.0000 1863.9500 0.6200 ;
      RECT 1848.2500 0.0000 1855.9500 0.6200 ;
      RECT 1840.2500 0.0000 1847.9500 0.6200 ;
      RECT 1832.2500 0.0000 1839.9500 0.6200 ;
      RECT 1824.2500 0.0000 1831.9500 0.6200 ;
      RECT 1816.2500 0.0000 1823.9500 0.6200 ;
      RECT 1808.2500 0.0000 1815.9500 0.6200 ;
      RECT 1800.2500 0.0000 1807.9500 0.6200 ;
      RECT 1792.2500 0.0000 1799.9500 0.6200 ;
      RECT 1784.2500 0.0000 1791.9500 0.6200 ;
      RECT 1776.2500 0.0000 1783.9500 0.6200 ;
      RECT 1768.2500 0.0000 1775.9500 0.6200 ;
      RECT 1760.2500 0.0000 1767.9500 0.6200 ;
      RECT 1752.2500 0.0000 1759.9500 0.6200 ;
      RECT 1744.2500 0.0000 1751.9500 0.6200 ;
      RECT 1736.2500 0.0000 1743.9500 0.6200 ;
      RECT 1728.2500 0.0000 1735.9500 0.6200 ;
      RECT 1720.2500 0.0000 1727.9500 0.6200 ;
      RECT 1712.2500 0.0000 1719.9500 0.6200 ;
      RECT 1704.2500 0.0000 1711.9500 0.6200 ;
      RECT 1696.2500 0.0000 1703.9500 0.6200 ;
      RECT 1688.2500 0.0000 1695.9500 0.6200 ;
      RECT 1680.2500 0.0000 1687.9500 0.6200 ;
      RECT 1672.2500 0.0000 1679.9500 0.6200 ;
      RECT 1664.2500 0.0000 1671.9500 0.6200 ;
      RECT 1656.2500 0.0000 1663.9500 0.6200 ;
      RECT 1648.2500 0.0000 1655.9500 0.6200 ;
      RECT 1640.2500 0.0000 1647.9500 0.6200 ;
      RECT 1632.2500 0.0000 1639.9500 0.6200 ;
      RECT 1624.2500 0.0000 1631.9500 0.6200 ;
      RECT 1616.2500 0.0000 1623.9500 0.6200 ;
      RECT 1608.2500 0.0000 1615.9500 0.6200 ;
      RECT 1600.2500 0.0000 1607.9500 0.6200 ;
      RECT 1592.2500 0.0000 1599.9500 0.6200 ;
      RECT 1584.2500 0.0000 1591.9500 0.6200 ;
      RECT 1576.2500 0.0000 1583.9500 0.6200 ;
      RECT 1568.2500 0.0000 1575.9500 0.6200 ;
      RECT 1560.2500 0.0000 1567.9500 0.6200 ;
      RECT 1552.2500 0.0000 1559.9500 0.6200 ;
      RECT 1544.2500 0.0000 1551.9500 0.6200 ;
      RECT 1536.2500 0.0000 1543.9500 0.6200 ;
      RECT 1528.2500 0.0000 1535.9500 0.6200 ;
      RECT 1520.2500 0.0000 1527.9500 0.6200 ;
      RECT 1512.2500 0.0000 1519.9500 0.6200 ;
      RECT 1504.2500 0.0000 1511.9500 0.6200 ;
      RECT 1496.2500 0.0000 1503.9500 0.6200 ;
      RECT 1488.2500 0.0000 1495.9500 0.6200 ;
      RECT 1480.2500 0.0000 1487.9500 0.6200 ;
      RECT 1472.2500 0.0000 1479.9500 0.6200 ;
      RECT 1464.2500 0.0000 1471.9500 0.6200 ;
      RECT 1456.2500 0.0000 1463.9500 0.6200 ;
      RECT 1448.2500 0.0000 1455.9500 0.6200 ;
      RECT 1440.2500 0.0000 1447.9500 0.6200 ;
      RECT 1432.2500 0.0000 1439.9500 0.6200 ;
      RECT 1424.2500 0.0000 1431.9500 0.6200 ;
      RECT 1416.2500 0.0000 1423.9500 0.6200 ;
      RECT 1408.2500 0.0000 1415.9500 0.6200 ;
      RECT 1400.2500 0.0000 1407.9500 0.6200 ;
      RECT 1392.2500 0.0000 1399.9500 0.6200 ;
      RECT 1384.2500 0.0000 1391.9500 0.6200 ;
      RECT 1376.2500 0.0000 1383.9500 0.6200 ;
      RECT 1368.2500 0.0000 1375.9500 0.6200 ;
      RECT 1360.2500 0.0000 1367.9500 0.6200 ;
      RECT 1352.2500 0.0000 1359.9500 0.6200 ;
      RECT 1344.2500 0.0000 1351.9500 0.6200 ;
      RECT 1336.2500 0.0000 1343.9500 0.6200 ;
      RECT 1328.2500 0.0000 1335.9500 0.6200 ;
      RECT 1320.2500 0.0000 1327.9500 0.6200 ;
      RECT 1312.2500 0.0000 1319.9500 0.6200 ;
      RECT 1304.2500 0.0000 1311.9500 0.6200 ;
      RECT 1296.2500 0.0000 1303.9500 0.6200 ;
      RECT 1288.2500 0.0000 1295.9500 0.6200 ;
      RECT 1280.2500 0.0000 1287.9500 0.6200 ;
      RECT 1272.2500 0.0000 1279.9500 0.6200 ;
      RECT 1264.2500 0.0000 1271.9500 0.6200 ;
      RECT 1256.2500 0.0000 1263.9500 0.6200 ;
      RECT 1248.2500 0.0000 1255.9500 0.6200 ;
      RECT 1240.2500 0.0000 1247.9500 0.6200 ;
      RECT 1232.2500 0.0000 1239.9500 0.6200 ;
      RECT 1224.2500 0.0000 1231.9500 0.6200 ;
      RECT 1216.2500 0.0000 1223.9500 0.6200 ;
      RECT 1208.2500 0.0000 1215.9500 0.6200 ;
      RECT 1200.2500 0.0000 1207.9500 0.6200 ;
      RECT 1192.2500 0.0000 1199.9500 0.6200 ;
      RECT 1184.2500 0.0000 1191.9500 0.6200 ;
      RECT 1176.2500 0.0000 1183.9500 0.6200 ;
      RECT 1168.2500 0.0000 1175.9500 0.6200 ;
      RECT 1160.2500 0.0000 1167.9500 0.6200 ;
      RECT 1152.2500 0.0000 1159.9500 0.6200 ;
      RECT 1144.2500 0.0000 1151.9500 0.6200 ;
      RECT 1136.2500 0.0000 1143.9500 0.6200 ;
      RECT 1128.2500 0.0000 1135.9500 0.6200 ;
      RECT 1120.2500 0.0000 1127.9500 0.6200 ;
      RECT 1112.2500 0.0000 1119.9500 0.6200 ;
      RECT 1104.2500 0.0000 1111.9500 0.6200 ;
      RECT 1096.2500 0.0000 1103.9500 0.6200 ;
      RECT 1088.2500 0.0000 1095.9500 0.6200 ;
      RECT 1080.2500 0.0000 1087.9500 0.6200 ;
      RECT 1072.2500 0.0000 1079.9500 0.6200 ;
      RECT 1064.2500 0.0000 1071.9500 0.6200 ;
      RECT 1056.2500 0.0000 1063.9500 0.6200 ;
      RECT 1048.2500 0.0000 1055.9500 0.6200 ;
      RECT 1040.2500 0.0000 1047.9500 0.6200 ;
      RECT 1032.2500 0.0000 1039.9500 0.6200 ;
      RECT 1024.2500 0.0000 1031.9500 0.6200 ;
      RECT 1016.2500 0.0000 1023.9500 0.6200 ;
      RECT 1008.2500 0.0000 1015.9500 0.6200 ;
      RECT 1000.2500 0.0000 1007.9500 0.6200 ;
      RECT 992.2500 0.0000 999.9500 0.6200 ;
      RECT 984.2500 0.0000 991.9500 0.6200 ;
      RECT 976.2500 0.0000 983.9500 0.6200 ;
      RECT 968.2500 0.0000 975.9500 0.6200 ;
      RECT 960.2500 0.0000 967.9500 0.6200 ;
      RECT 952.2500 0.0000 959.9500 0.6200 ;
      RECT 944.2500 0.0000 951.9500 0.6200 ;
      RECT 936.2500 0.0000 943.9500 0.6200 ;
      RECT 928.2500 0.0000 935.9500 0.6200 ;
      RECT 920.2500 0.0000 927.9500 0.6200 ;
      RECT 912.2500 0.0000 919.9500 0.6200 ;
      RECT 904.2500 0.0000 911.9500 0.6200 ;
      RECT 896.2500 0.0000 903.9500 0.6200 ;
      RECT 888.2500 0.0000 895.9500 0.6200 ;
      RECT 880.2500 0.0000 887.9500 0.6200 ;
      RECT 872.2500 0.0000 879.9500 0.6200 ;
      RECT 864.2500 0.0000 871.9500 0.6200 ;
      RECT 856.2500 0.0000 863.9500 0.6200 ;
      RECT 848.2500 0.0000 855.9500 0.6200 ;
      RECT 840.2500 0.0000 847.9500 0.6200 ;
      RECT 832.2500 0.0000 839.9500 0.6200 ;
      RECT 824.2500 0.0000 831.9500 0.6200 ;
      RECT 816.2500 0.0000 823.9500 0.6200 ;
      RECT 808.2500 0.0000 815.9500 0.6200 ;
      RECT 800.2500 0.0000 807.9500 0.6200 ;
      RECT 792.2500 0.0000 799.9500 0.6200 ;
      RECT 784.2500 0.0000 791.9500 0.6200 ;
      RECT 776.2500 0.0000 783.9500 0.6200 ;
      RECT 768.2500 0.0000 775.9500 0.6200 ;
      RECT 760.2500 0.0000 767.9500 0.6200 ;
      RECT 752.2500 0.0000 759.9500 0.6200 ;
      RECT 0.0000 0.0000 751.9500 0.6200 ;
    LAYER M5 ;
      RECT 0.0000 0.0000 2840.0000 1640.0000 ;
    LAYER M6 ;
      RECT 0.0000 0.0000 2840.0000 1640.0000 ;
    LAYER M7 ;
      RECT 0.0000 0.0000 2840.0000 1640.0000 ;
    LAYER M8 ;
      RECT 0.0000 0.0000 2840.0000 1640.0000 ;
  END
END fullchip

END LIBRARY
